VERSION 5.7 ;
  NOWIREEXTENSIONATPIN ON ;
  DIVIDERCHAR "/" ;
  BUSBITCHARS "[]" ;
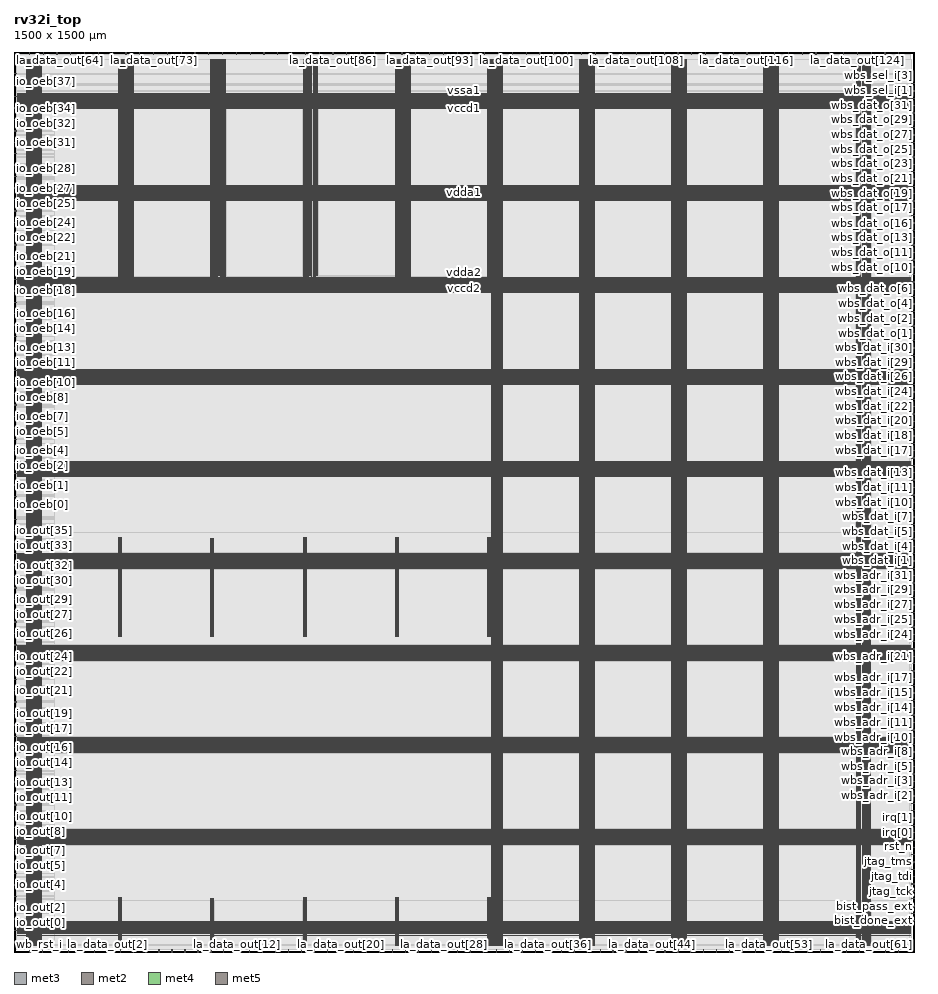
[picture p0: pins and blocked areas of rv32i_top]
MACRO rv32i_top
  CLASS BLOCK ;
  FOREIGN rv32i_top ;
  ORIGIN 0.000 0.000 ;
  SIZE 1500.000 BY 1500.000 ;
  PIN bist_done_ext
    DIRECTION OUTPUT TRISTATE ;
    USE SIGNAL ;
    PORT
      LAYER met3 ;
        RECT 1496.000 51.720 1500.000 52.320 ;
    END
  END bist_done_ext
  PIN bist_mode_ext
    DIRECTION INPUT ;
    USE SIGNAL ;
    PORT
      LAYER met3 ;
        RECT 1496.000 63.960 1500.000 64.560 ;
    END
  END bist_mode_ext
  PIN bist_pass_ext
    DIRECTION OUTPUT TRISTATE ;
    USE SIGNAL ;
    PORT
      LAYER met3 ;
        RECT 1496.000 76.200 1500.000 76.800 ;
    END
  END bist_pass_ext
  PIN clk
    DIRECTION INPUT ;
    USE SIGNAL ;
    ANTENNAGATEAREA 1.286700 ;
    ANTENNADIFFAREA 0.434700 ;
    PORT
      LAYER met3 ;
        RECT 1496.000 88.440 1500.000 89.040 ;
    END
  END clk
  PIN io_oeb[0]
    DIRECTION OUTPUT TRISTATE ;
    USE SIGNAL ;
    PORT
      LAYER met3 ;
        RECT 0.000 758.920 4.000 759.520 ;
    END
  END io_oeb[0]
  PIN io_oeb[10]
    DIRECTION OUTPUT TRISTATE ;
    USE SIGNAL ;
    PORT
      LAYER met3 ;
        RECT 0.000 949.320 4.000 949.920 ;
    END
  END io_oeb[10]
  PIN io_oeb[11]
    DIRECTION OUTPUT TRISTATE ;
    USE SIGNAL ;
    PORT
      LAYER met3 ;
        RECT 0.000 968.360 4.000 968.960 ;
    END
  END io_oeb[11]
  PIN io_oeb[12]
    DIRECTION OUTPUT TRISTATE ;
    USE SIGNAL ;
    PORT
      LAYER met3 ;
        RECT 0.000 987.400 4.000 988.000 ;
    END
  END io_oeb[12]
  PIN io_oeb[13]
    DIRECTION OUTPUT TRISTATE ;
    USE SIGNAL ;
    PORT
      LAYER met3 ;
        RECT 0.000 1006.440 4.000 1007.040 ;
    END
  END io_oeb[13]
  PIN io_oeb[14]
    DIRECTION OUTPUT TRISTATE ;
    USE SIGNAL ;
    PORT
      LAYER met3 ;
        RECT 0.000 1025.480 4.000 1026.080 ;
    END
  END io_oeb[14]
  PIN io_oeb[15]
    DIRECTION OUTPUT TRISTATE ;
    USE SIGNAL ;
    PORT
      LAYER met3 ;
        RECT 0.000 1044.520 4.000 1045.120 ;
    END
  END io_oeb[15]
  PIN io_oeb[16]
    DIRECTION OUTPUT TRISTATE ;
    USE SIGNAL ;
    PORT
      LAYER met3 ;
        RECT 0.000 1063.560 4.000 1064.160 ;
    END
  END io_oeb[16]
  PIN io_oeb[17]
    DIRECTION OUTPUT TRISTATE ;
    USE SIGNAL ;
    PORT
      LAYER met3 ;
        RECT 0.000 1082.600 4.000 1083.200 ;
    END
  END io_oeb[17]
  PIN io_oeb[18]
    DIRECTION OUTPUT TRISTATE ;
    USE SIGNAL ;
    PORT
      LAYER met3 ;
        RECT 0.000 1101.640 4.000 1102.240 ;
    END
  END io_oeb[18]
  PIN io_oeb[19]
    DIRECTION OUTPUT TRISTATE ;
    USE SIGNAL ;
    PORT
      LAYER met3 ;
        RECT 0.000 1120.680 4.000 1121.280 ;
    END
  END io_oeb[19]
  PIN io_oeb[1]
    DIRECTION OUTPUT TRISTATE ;
    USE SIGNAL ;
    PORT
      LAYER met3 ;
        RECT 0.000 777.960 4.000 778.560 ;
    END
  END io_oeb[1]
  PIN io_oeb[20]
    DIRECTION OUTPUT TRISTATE ;
    USE SIGNAL ;
    PORT
      LAYER met3 ;
        RECT 0.000 1139.720 4.000 1140.320 ;
    END
  END io_oeb[20]
  PIN io_oeb[21]
    DIRECTION OUTPUT TRISTATE ;
    USE SIGNAL ;
    PORT
      LAYER met3 ;
        RECT 0.000 1158.760 4.000 1159.360 ;
    END
  END io_oeb[21]
  PIN io_oeb[22]
    DIRECTION OUTPUT TRISTATE ;
    USE SIGNAL ;
    PORT
      LAYER met3 ;
        RECT 0.000 1177.800 4.000 1178.400 ;
    END
  END io_oeb[22]
  PIN io_oeb[23]
    DIRECTION OUTPUT TRISTATE ;
    USE SIGNAL ;
    PORT
      LAYER met3 ;
        RECT 0.000 1196.840 4.000 1197.440 ;
    END
  END io_oeb[23]
  PIN io_oeb[24]
    DIRECTION OUTPUT TRISTATE ;
    USE SIGNAL ;
    PORT
      LAYER met3 ;
        RECT 0.000 1215.880 4.000 1216.480 ;
    END
  END io_oeb[24]
  PIN io_oeb[25]
    DIRECTION OUTPUT TRISTATE ;
    USE SIGNAL ;
    PORT
      LAYER met3 ;
        RECT 0.000 1234.920 4.000 1235.520 ;
    END
  END io_oeb[25]
  PIN io_oeb[26]
    DIRECTION OUTPUT TRISTATE ;
    USE SIGNAL ;
    PORT
      LAYER met3 ;
        RECT 0.000 1253.960 4.000 1254.560 ;
    END
  END io_oeb[26]
  PIN io_oeb[27]
    DIRECTION OUTPUT TRISTATE ;
    USE SIGNAL ;
    PORT
      LAYER met3 ;
        RECT 0.000 1273.000 4.000 1273.600 ;
    END
  END io_oeb[27]
  PIN io_oeb[28]
    DIRECTION OUTPUT TRISTATE ;
    USE SIGNAL ;
    PORT
      LAYER met3 ;
        RECT 0.000 1292.040 4.000 1292.640 ;
    END
  END io_oeb[28]
  PIN io_oeb[29]
    DIRECTION OUTPUT TRISTATE ;
    USE SIGNAL ;
    PORT
      LAYER met3 ;
        RECT 0.000 1311.080 4.000 1311.680 ;
    END
  END io_oeb[29]
  PIN io_oeb[2]
    DIRECTION OUTPUT TRISTATE ;
    USE SIGNAL ;
    PORT
      LAYER met3 ;
        RECT 0.000 797.000 4.000 797.600 ;
    END
  END io_oeb[2]
  PIN io_oeb[30]
    DIRECTION OUTPUT TRISTATE ;
    USE SIGNAL ;
    PORT
      LAYER met3 ;
        RECT 0.000 1330.120 4.000 1330.720 ;
    END
  END io_oeb[30]
  PIN io_oeb[31]
    DIRECTION OUTPUT TRISTATE ;
    USE SIGNAL ;
    PORT
      LAYER met3 ;
        RECT 0.000 1349.160 4.000 1349.760 ;
    END
  END io_oeb[31]
  PIN io_oeb[32]
    DIRECTION OUTPUT TRISTATE ;
    USE SIGNAL ;
    PORT
      LAYER met3 ;
        RECT 0.000 1368.200 4.000 1368.800 ;
    END
  END io_oeb[32]
  PIN io_oeb[33]
    DIRECTION OUTPUT TRISTATE ;
    USE SIGNAL ;
    PORT
      LAYER met3 ;
        RECT 0.000 1387.240 4.000 1387.840 ;
    END
  END io_oeb[33]
  PIN io_oeb[34]
    DIRECTION OUTPUT TRISTATE ;
    USE SIGNAL ;
    PORT
      LAYER met3 ;
        RECT 0.000 1406.280 4.000 1406.880 ;
    END
  END io_oeb[34]
  PIN io_oeb[35]
    DIRECTION OUTPUT TRISTATE ;
    USE SIGNAL ;
    PORT
      LAYER met3 ;
        RECT 0.000 1425.320 4.000 1425.920 ;
    END
  END io_oeb[35]
  PIN io_oeb[36]
    DIRECTION OUTPUT TRISTATE ;
    USE SIGNAL ;
    PORT
      LAYER met3 ;
        RECT 0.000 1444.360 4.000 1444.960 ;
    END
  END io_oeb[36]
  PIN io_oeb[37]
    DIRECTION OUTPUT TRISTATE ;
    USE SIGNAL ;
    PORT
      LAYER met3 ;
        RECT 0.000 1463.400 4.000 1464.000 ;
    END
  END io_oeb[37]
  PIN io_oeb[3]
    DIRECTION OUTPUT TRISTATE ;
    USE SIGNAL ;
    PORT
      LAYER met3 ;
        RECT 0.000 816.040 4.000 816.640 ;
    END
  END io_oeb[3]
  PIN io_oeb[4]
    DIRECTION OUTPUT TRISTATE ;
    USE SIGNAL ;
    PORT
      LAYER met3 ;
        RECT 0.000 835.080 4.000 835.680 ;
    END
  END io_oeb[4]
  PIN io_oeb[5]
    DIRECTION OUTPUT TRISTATE ;
    USE SIGNAL ;
    PORT
      LAYER met3 ;
        RECT 0.000 854.120 4.000 854.720 ;
    END
  END io_oeb[5]
  PIN io_oeb[6]
    DIRECTION OUTPUT TRISTATE ;
    USE SIGNAL ;
    PORT
      LAYER met3 ;
        RECT 0.000 873.160 4.000 873.760 ;
    END
  END io_oeb[6]
  PIN io_oeb[7]
    DIRECTION OUTPUT TRISTATE ;
    USE SIGNAL ;
    PORT
      LAYER met3 ;
        RECT 0.000 892.200 4.000 892.800 ;
    END
  END io_oeb[7]
  PIN io_oeb[8]
    DIRECTION OUTPUT TRISTATE ;
    USE SIGNAL ;
    PORT
      LAYER met3 ;
        RECT 0.000 911.240 4.000 911.840 ;
    END
  END io_oeb[8]
  PIN io_oeb[9]
    DIRECTION OUTPUT TRISTATE ;
    USE SIGNAL ;
    PORT
      LAYER met3 ;
        RECT 0.000 930.280 4.000 930.880 ;
    END
  END io_oeb[9]
  PIN io_out[0]
    DIRECTION OUTPUT TRISTATE ;
    USE SIGNAL ;
    PORT
      LAYER met3 ;
        RECT 0.000 35.400 4.000 36.000 ;
    END
  END io_out[0]
  PIN io_out[10]
    DIRECTION OUTPUT TRISTATE ;
    USE SIGNAL ;
    PORT
      LAYER met3 ;
        RECT 0.000 225.800 4.000 226.400 ;
    END
  END io_out[10]
  PIN io_out[11]
    DIRECTION OUTPUT TRISTATE ;
    USE SIGNAL ;
    PORT
      LAYER met3 ;
        RECT 0.000 244.840 4.000 245.440 ;
    END
  END io_out[11]
  PIN io_out[12]
    DIRECTION OUTPUT TRISTATE ;
    USE SIGNAL ;
    PORT
      LAYER met3 ;
        RECT 0.000 263.880 4.000 264.480 ;
    END
  END io_out[12]
  PIN io_out[13]
    DIRECTION OUTPUT TRISTATE ;
    USE SIGNAL ;
    PORT
      LAYER met3 ;
        RECT 0.000 282.920 4.000 283.520 ;
    END
  END io_out[13]
  PIN io_out[14]
    DIRECTION OUTPUT TRISTATE ;
    USE SIGNAL ;
    PORT
      LAYER met3 ;
        RECT 0.000 301.960 4.000 302.560 ;
    END
  END io_out[14]
  PIN io_out[15]
    DIRECTION OUTPUT TRISTATE ;
    USE SIGNAL ;
    PORT
      LAYER met3 ;
        RECT 0.000 321.000 4.000 321.600 ;
    END
  END io_out[15]
  PIN io_out[16]
    DIRECTION OUTPUT TRISTATE ;
    USE SIGNAL ;
    PORT
      LAYER met3 ;
        RECT 0.000 340.040 4.000 340.640 ;
    END
  END io_out[16]
  PIN io_out[17]
    DIRECTION OUTPUT TRISTATE ;
    USE SIGNAL ;
    PORT
      LAYER met3 ;
        RECT 0.000 359.080 4.000 359.680 ;
    END
  END io_out[17]
  PIN io_out[18]
    DIRECTION OUTPUT TRISTATE ;
    USE SIGNAL ;
    PORT
      LAYER met3 ;
        RECT 0.000 378.120 4.000 378.720 ;
    END
  END io_out[18]
  PIN io_out[19]
    DIRECTION OUTPUT TRISTATE ;
    USE SIGNAL ;
    PORT
      LAYER met3 ;
        RECT 0.000 397.160 4.000 397.760 ;
    END
  END io_out[19]
  PIN io_out[1]
    DIRECTION OUTPUT TRISTATE ;
    USE SIGNAL ;
    PORT
      LAYER met3 ;
        RECT 0.000 54.440 4.000 55.040 ;
    END
  END io_out[1]
  PIN io_out[20]
    DIRECTION OUTPUT TRISTATE ;
    USE SIGNAL ;
    PORT
      LAYER met3 ;
        RECT 0.000 416.200 4.000 416.800 ;
    END
  END io_out[20]
  PIN io_out[21]
    DIRECTION OUTPUT TRISTATE ;
    USE SIGNAL ;
    PORT
      LAYER met3 ;
        RECT 0.000 435.240 4.000 435.840 ;
    END
  END io_out[21]
  PIN io_out[22]
    DIRECTION OUTPUT TRISTATE ;
    USE SIGNAL ;
    PORT
      LAYER met3 ;
        RECT 0.000 454.280 4.000 454.880 ;
    END
  END io_out[22]
  PIN io_out[23]
    DIRECTION OUTPUT TRISTATE ;
    USE SIGNAL ;
    PORT
      LAYER met3 ;
        RECT 0.000 473.320 4.000 473.920 ;
    END
  END io_out[23]
  PIN io_out[24]
    DIRECTION OUTPUT TRISTATE ;
    USE SIGNAL ;
    PORT
      LAYER met3 ;
        RECT 0.000 492.360 4.000 492.960 ;
    END
  END io_out[24]
  PIN io_out[25]
    DIRECTION OUTPUT TRISTATE ;
    USE SIGNAL ;
    PORT
      LAYER met3 ;
        RECT 0.000 511.400 4.000 512.000 ;
    END
  END io_out[25]
  PIN io_out[26]
    DIRECTION OUTPUT TRISTATE ;
    USE SIGNAL ;
    PORT
      LAYER met3 ;
        RECT 0.000 530.440 4.000 531.040 ;
    END
  END io_out[26]
  PIN io_out[27]
    DIRECTION OUTPUT TRISTATE ;
    USE SIGNAL ;
    PORT
      LAYER met3 ;
        RECT 0.000 549.480 4.000 550.080 ;
    END
  END io_out[27]
  PIN io_out[28]
    DIRECTION OUTPUT TRISTATE ;
    USE SIGNAL ;
    PORT
      LAYER met3 ;
        RECT 0.000 568.520 4.000 569.120 ;
    END
  END io_out[28]
  PIN io_out[29]
    DIRECTION OUTPUT TRISTATE ;
    USE SIGNAL ;
    PORT
      LAYER met3 ;
        RECT 0.000 587.560 4.000 588.160 ;
    END
  END io_out[29]
  PIN io_out[2]
    DIRECTION OUTPUT TRISTATE ;
    USE SIGNAL ;
    PORT
      LAYER met3 ;
        RECT 0.000 73.480 4.000 74.080 ;
    END
  END io_out[2]
  PIN io_out[30]
    DIRECTION OUTPUT TRISTATE ;
    USE SIGNAL ;
    PORT
      LAYER met3 ;
        RECT 0.000 606.600 4.000 607.200 ;
    END
  END io_out[30]
  PIN io_out[31]
    DIRECTION OUTPUT TRISTATE ;
    USE SIGNAL ;
    PORT
      LAYER met3 ;
        RECT 0.000 625.640 4.000 626.240 ;
    END
  END io_out[31]
  PIN io_out[32]
    DIRECTION OUTPUT TRISTATE ;
    USE SIGNAL ;
    PORT
      LAYER met3 ;
        RECT 0.000 644.680 4.000 645.280 ;
    END
  END io_out[32]
  PIN io_out[33]
    DIRECTION OUTPUT TRISTATE ;
    USE SIGNAL ;
    PORT
      LAYER met3 ;
        RECT 0.000 663.720 4.000 664.320 ;
    END
  END io_out[33]
  PIN io_out[34]
    DIRECTION OUTPUT TRISTATE ;
    USE SIGNAL ;
    PORT
      LAYER met3 ;
        RECT 0.000 682.760 4.000 683.360 ;
    END
  END io_out[34]
  PIN io_out[35]
    DIRECTION OUTPUT TRISTATE ;
    USE SIGNAL ;
    PORT
      LAYER met3 ;
        RECT 0.000 701.800 4.000 702.400 ;
    END
  END io_out[35]
  PIN io_out[36]
    DIRECTION OUTPUT TRISTATE ;
    USE SIGNAL ;
    PORT
      LAYER met3 ;
        RECT 0.000 720.840 4.000 721.440 ;
    END
  END io_out[36]
  PIN io_out[37]
    DIRECTION OUTPUT TRISTATE ;
    USE SIGNAL ;
    PORT
      LAYER met3 ;
        RECT 0.000 739.880 4.000 740.480 ;
    END
  END io_out[37]
  PIN io_out[3]
    DIRECTION OUTPUT TRISTATE ;
    USE SIGNAL ;
    PORT
      LAYER met3 ;
        RECT 0.000 92.520 4.000 93.120 ;
    END
  END io_out[3]
  PIN io_out[4]
    DIRECTION OUTPUT TRISTATE ;
    USE SIGNAL ;
    PORT
      LAYER met3 ;
        RECT 0.000 111.560 4.000 112.160 ;
    END
  END io_out[4]
  PIN io_out[5]
    DIRECTION OUTPUT TRISTATE ;
    USE SIGNAL ;
    PORT
      LAYER met3 ;
        RECT 0.000 130.600 4.000 131.200 ;
    END
  END io_out[5]
  PIN io_out[6]
    DIRECTION OUTPUT TRISTATE ;
    USE SIGNAL ;
    PORT
      LAYER met3 ;
        RECT 0.000 149.640 4.000 150.240 ;
    END
  END io_out[6]
  PIN io_out[7]
    DIRECTION OUTPUT TRISTATE ;
    USE SIGNAL ;
    PORT
      LAYER met3 ;
        RECT 0.000 168.680 4.000 169.280 ;
    END
  END io_out[7]
  PIN io_out[8]
    DIRECTION OUTPUT TRISTATE ;
    USE SIGNAL ;
    PORT
      LAYER met3 ;
        RECT 0.000 187.720 4.000 188.320 ;
    END
  END io_out[8]
  PIN io_out[9]
    DIRECTION OUTPUT TRISTATE ;
    USE SIGNAL ;
    PORT
      LAYER met3 ;
        RECT 0.000 206.760 4.000 207.360 ;
    END
  END io_out[9]
  PIN irq[0]
    DIRECTION OUTPUT TRISTATE ;
    USE SIGNAL ;
    PORT
      LAYER met3 ;
        RECT 1496.000 198.600 1500.000 199.200 ;
    END
  END irq[0]
  PIN irq[1]
    DIRECTION OUTPUT TRISTATE ;
    USE SIGNAL ;
    PORT
      LAYER met3 ;
        RECT 1496.000 210.840 1500.000 211.440 ;
    END
  END irq[1]
  PIN irq[2]
    DIRECTION OUTPUT TRISTATE ;
    USE SIGNAL ;
    PORT
      LAYER met3 ;
        RECT 1496.000 223.080 1500.000 223.680 ;
    END
  END irq[2]
  PIN jtag_tck
    DIRECTION INPUT ;
    USE SIGNAL ;
    PORT
      LAYER met3 ;
        RECT 1496.000 100.680 1500.000 101.280 ;
    END
  END jtag_tck
  PIN jtag_tdi
    DIRECTION INPUT ;
    USE SIGNAL ;
    PORT
      LAYER met3 ;
        RECT 1496.000 112.920 1500.000 113.520 ;
    END
  END jtag_tdi
  PIN jtag_tdo
    DIRECTION OUTPUT TRISTATE ;
    USE SIGNAL ;
    PORT
      LAYER met3 ;
        RECT 1496.000 125.160 1500.000 125.760 ;
    END
  END jtag_tdo
  PIN jtag_tms
    DIRECTION INPUT ;
    USE SIGNAL ;
    PORT
      LAYER met3 ;
        RECT 1496.000 137.400 1500.000 138.000 ;
    END
  END jtag_tms
  PIN jtag_trst_n
    DIRECTION INPUT ;
    USE SIGNAL ;
    PORT
      LAYER met3 ;
        RECT 1496.000 149.640 1500.000 150.240 ;
    END
  END jtag_trst_n
  PIN la_data_out[0]
    DIRECTION OUTPUT TRISTATE ;
    USE SIGNAL ;
    PORT
      LAYER met2 ;
        RECT 111.870 0.000 112.150 4.000 ;
    END
  END la_data_out[0]
  PIN la_data_out[100]
    DIRECTION OUTPUT TRISTATE ;
    USE SIGNAL ;
    PORT
      LAYER met2 ;
        RECT 853.390 1496.000 853.670 1500.000 ;
    END
  END la_data_out[100]
  PIN la_data_out[101]
    DIRECTION OUTPUT TRISTATE ;
    USE SIGNAL ;
    PORT
      LAYER met2 ;
        RECT 876.390 1496.000 876.670 1500.000 ;
    END
  END la_data_out[101]
  PIN la_data_out[102]
    DIRECTION OUTPUT TRISTATE ;
    USE SIGNAL ;
    PORT
      LAYER met2 ;
        RECT 899.390 1496.000 899.670 1500.000 ;
    END
  END la_data_out[102]
  PIN la_data_out[103]
    DIRECTION OUTPUT TRISTATE ;
    USE SIGNAL ;
    PORT
      LAYER met2 ;
        RECT 922.390 1496.000 922.670 1500.000 ;
    END
  END la_data_out[103]
  PIN la_data_out[104]
    DIRECTION OUTPUT TRISTATE ;
    USE SIGNAL ;
    PORT
      LAYER met2 ;
        RECT 945.390 1496.000 945.670 1500.000 ;
    END
  END la_data_out[104]
  PIN la_data_out[105]
    DIRECTION OUTPUT TRISTATE ;
    USE SIGNAL ;
    PORT
      LAYER met2 ;
        RECT 968.390 1496.000 968.670 1500.000 ;
    END
  END la_data_out[105]
  PIN la_data_out[106]
    DIRECTION OUTPUT TRISTATE ;
    USE SIGNAL ;
    PORT
      LAYER met2 ;
        RECT 991.390 1496.000 991.670 1500.000 ;
    END
  END la_data_out[106]
  PIN la_data_out[107]
    DIRECTION OUTPUT TRISTATE ;
    USE SIGNAL ;
    PORT
      LAYER met2 ;
        RECT 1014.390 1496.000 1014.670 1500.000 ;
    END
  END la_data_out[107]
  PIN la_data_out[108]
    DIRECTION OUTPUT TRISTATE ;
    USE SIGNAL ;
    PORT
      LAYER met2 ;
        RECT 1037.390 1496.000 1037.670 1500.000 ;
    END
  END la_data_out[108]
  PIN la_data_out[109]
    DIRECTION OUTPUT TRISTATE ;
    USE SIGNAL ;
    PORT
      LAYER met2 ;
        RECT 1060.390 1496.000 1060.670 1500.000 ;
    END
  END la_data_out[109]
  PIN la_data_out[10]
    DIRECTION OUTPUT TRISTATE ;
    USE SIGNAL ;
    PORT
      LAYER met2 ;
        RECT 328.070 0.000 328.350 4.000 ;
    END
  END la_data_out[10]
  PIN la_data_out[110]
    DIRECTION OUTPUT TRISTATE ;
    USE SIGNAL ;
    PORT
      LAYER met2 ;
        RECT 1083.390 1496.000 1083.670 1500.000 ;
    END
  END la_data_out[110]
  PIN la_data_out[111]
    DIRECTION OUTPUT TRISTATE ;
    USE SIGNAL ;
    PORT
      LAYER met2 ;
        RECT 1106.390 1496.000 1106.670 1500.000 ;
    END
  END la_data_out[111]
  PIN la_data_out[112]
    DIRECTION OUTPUT TRISTATE ;
    USE SIGNAL ;
    PORT
      LAYER met2 ;
        RECT 1129.390 1496.000 1129.670 1500.000 ;
    END
  END la_data_out[112]
  PIN la_data_out[113]
    DIRECTION OUTPUT TRISTATE ;
    USE SIGNAL ;
    PORT
      LAYER met2 ;
        RECT 1152.390 1496.000 1152.670 1500.000 ;
    END
  END la_data_out[113]
  PIN la_data_out[114]
    DIRECTION OUTPUT TRISTATE ;
    USE SIGNAL ;
    PORT
      LAYER met2 ;
        RECT 1175.390 1496.000 1175.670 1500.000 ;
    END
  END la_data_out[114]
  PIN la_data_out[115]
    DIRECTION OUTPUT TRISTATE ;
    USE SIGNAL ;
    PORT
      LAYER met2 ;
        RECT 1198.390 1496.000 1198.670 1500.000 ;
    END
  END la_data_out[115]
  PIN la_data_out[116]
    DIRECTION OUTPUT TRISTATE ;
    USE SIGNAL ;
    PORT
      LAYER met2 ;
        RECT 1221.390 1496.000 1221.670 1500.000 ;
    END
  END la_data_out[116]
  PIN la_data_out[117]
    DIRECTION OUTPUT TRISTATE ;
    USE SIGNAL ;
    PORT
      LAYER met2 ;
        RECT 1244.390 1496.000 1244.670 1500.000 ;
    END
  END la_data_out[117]
  PIN la_data_out[118]
    DIRECTION OUTPUT TRISTATE ;
    USE SIGNAL ;
    PORT
      LAYER met2 ;
        RECT 1267.390 1496.000 1267.670 1500.000 ;
    END
  END la_data_out[118]
  PIN la_data_out[119]
    DIRECTION OUTPUT TRISTATE ;
    USE SIGNAL ;
    PORT
      LAYER met2 ;
        RECT 1290.390 1496.000 1290.670 1500.000 ;
    END
  END la_data_out[119]
  PIN la_data_out[11]
    DIRECTION OUTPUT TRISTATE ;
    USE SIGNAL ;
    PORT
      LAYER met2 ;
        RECT 349.690 0.000 349.970 4.000 ;
    END
  END la_data_out[11]
  PIN la_data_out[120]
    DIRECTION OUTPUT TRISTATE ;
    USE SIGNAL ;
    PORT
      LAYER met2 ;
        RECT 1313.390 1496.000 1313.670 1500.000 ;
    END
  END la_data_out[120]
  PIN la_data_out[121]
    DIRECTION OUTPUT TRISTATE ;
    USE SIGNAL ;
    PORT
      LAYER met2 ;
        RECT 1336.390 1496.000 1336.670 1500.000 ;
    END
  END la_data_out[121]
  PIN la_data_out[122]
    DIRECTION OUTPUT TRISTATE ;
    USE SIGNAL ;
    PORT
      LAYER met2 ;
        RECT 1359.390 1496.000 1359.670 1500.000 ;
    END
  END la_data_out[122]
  PIN la_data_out[123]
    DIRECTION OUTPUT TRISTATE ;
    USE SIGNAL ;
    PORT
      LAYER met2 ;
        RECT 1382.390 1496.000 1382.670 1500.000 ;
    END
  END la_data_out[123]
  PIN la_data_out[124]
    DIRECTION OUTPUT TRISTATE ;
    USE SIGNAL ;
    PORT
      LAYER met2 ;
        RECT 1405.390 1496.000 1405.670 1500.000 ;
    END
  END la_data_out[124]
  PIN la_data_out[125]
    DIRECTION OUTPUT TRISTATE ;
    USE SIGNAL ;
    PORT
      LAYER met2 ;
        RECT 1428.390 1496.000 1428.670 1500.000 ;
    END
  END la_data_out[125]
  PIN la_data_out[126]
    DIRECTION OUTPUT TRISTATE ;
    USE SIGNAL ;
    PORT
      LAYER met2 ;
        RECT 1451.390 1496.000 1451.670 1500.000 ;
    END
  END la_data_out[126]
  PIN la_data_out[127]
    DIRECTION OUTPUT TRISTATE ;
    USE SIGNAL ;
    PORT
      LAYER met2 ;
        RECT 1474.390 1496.000 1474.670 1500.000 ;
    END
  END la_data_out[127]
  PIN la_data_out[12]
    DIRECTION OUTPUT TRISTATE ;
    USE SIGNAL ;
    PORT
      LAYER met2 ;
        RECT 371.310 0.000 371.590 4.000 ;
    END
  END la_data_out[12]
  PIN la_data_out[13]
    DIRECTION OUTPUT TRISTATE ;
    USE SIGNAL ;
    PORT
      LAYER met2 ;
        RECT 392.930 0.000 393.210 4.000 ;
    END
  END la_data_out[13]
  PIN la_data_out[14]
    DIRECTION OUTPUT TRISTATE ;
    USE SIGNAL ;
    PORT
      LAYER met2 ;
        RECT 414.550 0.000 414.830 4.000 ;
    END
  END la_data_out[14]
  PIN la_data_out[15]
    DIRECTION OUTPUT TRISTATE ;
    USE SIGNAL ;
    PORT
      LAYER met2 ;
        RECT 436.170 0.000 436.450 4.000 ;
    END
  END la_data_out[15]
  PIN la_data_out[16]
    DIRECTION OUTPUT TRISTATE ;
    USE SIGNAL ;
    PORT
      LAYER met2 ;
        RECT 457.790 0.000 458.070 4.000 ;
    END
  END la_data_out[16]
  PIN la_data_out[17]
    DIRECTION OUTPUT TRISTATE ;
    USE SIGNAL ;
    PORT
      LAYER met2 ;
        RECT 479.410 0.000 479.690 4.000 ;
    END
  END la_data_out[17]
  PIN la_data_out[18]
    DIRECTION OUTPUT TRISTATE ;
    USE SIGNAL ;
    PORT
      LAYER met2 ;
        RECT 501.030 0.000 501.310 4.000 ;
    END
  END la_data_out[18]
  PIN la_data_out[19]
    DIRECTION OUTPUT TRISTATE ;
    USE SIGNAL ;
    PORT
      LAYER met2 ;
        RECT 522.650 0.000 522.930 4.000 ;
    END
  END la_data_out[19]
  PIN la_data_out[1]
    DIRECTION OUTPUT TRISTATE ;
    USE SIGNAL ;
    PORT
      LAYER met2 ;
        RECT 133.490 0.000 133.770 4.000 ;
    END
  END la_data_out[1]
  PIN la_data_out[20]
    DIRECTION OUTPUT TRISTATE ;
    USE SIGNAL ;
    PORT
      LAYER met2 ;
        RECT 544.270 0.000 544.550 4.000 ;
    END
  END la_data_out[20]
  PIN la_data_out[21]
    DIRECTION OUTPUT TRISTATE ;
    USE SIGNAL ;
    PORT
      LAYER met2 ;
        RECT 565.890 0.000 566.170 4.000 ;
    END
  END la_data_out[21]
  PIN la_data_out[22]
    DIRECTION OUTPUT TRISTATE ;
    USE SIGNAL ;
    PORT
      LAYER met2 ;
        RECT 587.510 0.000 587.790 4.000 ;
    END
  END la_data_out[22]
  PIN la_data_out[23]
    DIRECTION OUTPUT TRISTATE ;
    USE SIGNAL ;
    PORT
      LAYER met2 ;
        RECT 609.130 0.000 609.410 4.000 ;
    END
  END la_data_out[23]
  PIN la_data_out[24]
    DIRECTION OUTPUT TRISTATE ;
    USE SIGNAL ;
    PORT
      LAYER met2 ;
        RECT 630.750 0.000 631.030 4.000 ;
    END
  END la_data_out[24]
  PIN la_data_out[25]
    DIRECTION OUTPUT TRISTATE ;
    USE SIGNAL ;
    PORT
      LAYER met2 ;
        RECT 652.370 0.000 652.650 4.000 ;
    END
  END la_data_out[25]
  PIN la_data_out[26]
    DIRECTION OUTPUT TRISTATE ;
    USE SIGNAL ;
    PORT
      LAYER met2 ;
        RECT 673.990 0.000 674.270 4.000 ;
    END
  END la_data_out[26]
  PIN la_data_out[27]
    DIRECTION OUTPUT TRISTATE ;
    USE SIGNAL ;
    PORT
      LAYER met2 ;
        RECT 695.610 0.000 695.890 4.000 ;
    END
  END la_data_out[27]
  PIN la_data_out[28]
    DIRECTION OUTPUT TRISTATE ;
    USE SIGNAL ;
    PORT
      LAYER met2 ;
        RECT 717.230 0.000 717.510 4.000 ;
    END
  END la_data_out[28]
  PIN la_data_out[29]
    DIRECTION OUTPUT TRISTATE ;
    USE SIGNAL ;
    PORT
      LAYER met2 ;
        RECT 738.850 0.000 739.130 4.000 ;
    END
  END la_data_out[29]
  PIN la_data_out[2]
    DIRECTION OUTPUT TRISTATE ;
    USE SIGNAL ;
    PORT
      LAYER met2 ;
        RECT 155.110 0.000 155.390 4.000 ;
    END
  END la_data_out[2]
  PIN la_data_out[30]
    DIRECTION OUTPUT TRISTATE ;
    USE SIGNAL ;
    PORT
      LAYER met2 ;
        RECT 760.470 0.000 760.750 4.000 ;
    END
  END la_data_out[30]
  PIN la_data_out[31]
    DIRECTION OUTPUT TRISTATE ;
    USE SIGNAL ;
    PORT
      LAYER met2 ;
        RECT 782.090 0.000 782.370 4.000 ;
    END
  END la_data_out[31]
  PIN la_data_out[32]
    DIRECTION OUTPUT TRISTATE ;
    USE SIGNAL ;
    PORT
      LAYER met2 ;
        RECT 803.710 0.000 803.990 4.000 ;
    END
  END la_data_out[32]
  PIN la_data_out[33]
    DIRECTION OUTPUT TRISTATE ;
    USE SIGNAL ;
    PORT
      LAYER met2 ;
        RECT 825.330 0.000 825.610 4.000 ;
    END
  END la_data_out[33]
  PIN la_data_out[34]
    DIRECTION OUTPUT TRISTATE ;
    USE SIGNAL ;
    PORT
      LAYER met2 ;
        RECT 846.950 0.000 847.230 4.000 ;
    END
  END la_data_out[34]
  PIN la_data_out[35]
    DIRECTION OUTPUT TRISTATE ;
    USE SIGNAL ;
    PORT
      LAYER met2 ;
        RECT 868.570 0.000 868.850 4.000 ;
    END
  END la_data_out[35]
  PIN la_data_out[36]
    DIRECTION OUTPUT TRISTATE ;
    USE SIGNAL ;
    PORT
      LAYER met2 ;
        RECT 890.190 0.000 890.470 4.000 ;
    END
  END la_data_out[36]
  PIN la_data_out[37]
    DIRECTION OUTPUT TRISTATE ;
    USE SIGNAL ;
    PORT
      LAYER met2 ;
        RECT 911.810 0.000 912.090 4.000 ;
    END
  END la_data_out[37]
  PIN la_data_out[38]
    DIRECTION OUTPUT TRISTATE ;
    USE SIGNAL ;
    PORT
      LAYER met2 ;
        RECT 933.430 0.000 933.710 4.000 ;
    END
  END la_data_out[38]
  PIN la_data_out[39]
    DIRECTION OUTPUT TRISTATE ;
    USE SIGNAL ;
    PORT
      LAYER met2 ;
        RECT 955.050 0.000 955.330 4.000 ;
    END
  END la_data_out[39]
  PIN la_data_out[3]
    DIRECTION OUTPUT TRISTATE ;
    USE SIGNAL ;
    PORT
      LAYER met2 ;
        RECT 176.730 0.000 177.010 4.000 ;
    END
  END la_data_out[3]
  PIN la_data_out[40]
    DIRECTION OUTPUT TRISTATE ;
    USE SIGNAL ;
    PORT
      LAYER met2 ;
        RECT 976.670 0.000 976.950 4.000 ;
    END
  END la_data_out[40]
  PIN la_data_out[41]
    DIRECTION OUTPUT TRISTATE ;
    USE SIGNAL ;
    PORT
      LAYER met2 ;
        RECT 998.290 0.000 998.570 4.000 ;
    END
  END la_data_out[41]
  PIN la_data_out[42]
    DIRECTION OUTPUT TRISTATE ;
    USE SIGNAL ;
    PORT
      LAYER met2 ;
        RECT 1019.910 0.000 1020.190 4.000 ;
    END
  END la_data_out[42]
  PIN la_data_out[43]
    DIRECTION OUTPUT TRISTATE ;
    USE SIGNAL ;
    PORT
      LAYER met2 ;
        RECT 1041.530 0.000 1041.810 4.000 ;
    END
  END la_data_out[43]
  PIN la_data_out[44]
    DIRECTION OUTPUT TRISTATE ;
    USE SIGNAL ;
    PORT
      LAYER met2 ;
        RECT 1063.150 0.000 1063.430 4.000 ;
    END
  END la_data_out[44]
  PIN la_data_out[45]
    DIRECTION OUTPUT TRISTATE ;
    USE SIGNAL ;
    PORT
      LAYER met2 ;
        RECT 1084.770 0.000 1085.050 4.000 ;
    END
  END la_data_out[45]
  PIN la_data_out[46]
    DIRECTION OUTPUT TRISTATE ;
    USE SIGNAL ;
    PORT
      LAYER met2 ;
        RECT 1106.390 0.000 1106.670 4.000 ;
    END
  END la_data_out[46]
  PIN la_data_out[47]
    DIRECTION OUTPUT TRISTATE ;
    USE SIGNAL ;
    PORT
      LAYER met2 ;
        RECT 1128.010 0.000 1128.290 4.000 ;
    END
  END la_data_out[47]
  PIN la_data_out[48]
    DIRECTION OUTPUT TRISTATE ;
    USE SIGNAL ;
    PORT
      LAYER met2 ;
        RECT 1149.630 0.000 1149.910 4.000 ;
    END
  END la_data_out[48]
  PIN la_data_out[49]
    DIRECTION OUTPUT TRISTATE ;
    USE SIGNAL ;
    PORT
      LAYER met2 ;
        RECT 1171.250 0.000 1171.530 4.000 ;
    END
  END la_data_out[49]
  PIN la_data_out[4]
    DIRECTION OUTPUT TRISTATE ;
    USE SIGNAL ;
    PORT
      LAYER met2 ;
        RECT 198.350 0.000 198.630 4.000 ;
    END
  END la_data_out[4]
  PIN la_data_out[50]
    DIRECTION OUTPUT TRISTATE ;
    USE SIGNAL ;
    PORT
      LAYER met2 ;
        RECT 1192.870 0.000 1193.150 4.000 ;
    END
  END la_data_out[50]
  PIN la_data_out[51]
    DIRECTION OUTPUT TRISTATE ;
    USE SIGNAL ;
    PORT
      LAYER met2 ;
        RECT 1214.490 0.000 1214.770 4.000 ;
    END
  END la_data_out[51]
  PIN la_data_out[52]
    DIRECTION OUTPUT TRISTATE ;
    USE SIGNAL ;
    PORT
      LAYER met2 ;
        RECT 1236.110 0.000 1236.390 4.000 ;
    END
  END la_data_out[52]
  PIN la_data_out[53]
    DIRECTION OUTPUT TRISTATE ;
    USE SIGNAL ;
    PORT
      LAYER met2 ;
        RECT 1257.730 0.000 1258.010 4.000 ;
    END
  END la_data_out[53]
  PIN la_data_out[54]
    DIRECTION OUTPUT TRISTATE ;
    USE SIGNAL ;
    PORT
      LAYER met2 ;
        RECT 1279.350 0.000 1279.630 4.000 ;
    END
  END la_data_out[54]
  PIN la_data_out[55]
    DIRECTION OUTPUT TRISTATE ;
    USE SIGNAL ;
    PORT
      LAYER met2 ;
        RECT 1300.970 0.000 1301.250 4.000 ;
    END
  END la_data_out[55]
  PIN la_data_out[56]
    DIRECTION OUTPUT TRISTATE ;
    USE SIGNAL ;
    PORT
      LAYER met2 ;
        RECT 1322.590 0.000 1322.870 4.000 ;
    END
  END la_data_out[56]
  PIN la_data_out[57]
    DIRECTION OUTPUT TRISTATE ;
    USE SIGNAL ;
    PORT
      LAYER met2 ;
        RECT 1344.210 0.000 1344.490 4.000 ;
    END
  END la_data_out[57]
  PIN la_data_out[58]
    DIRECTION OUTPUT TRISTATE ;
    USE SIGNAL ;
    PORT
      LAYER met2 ;
        RECT 1365.830 0.000 1366.110 4.000 ;
    END
  END la_data_out[58]
  PIN la_data_out[59]
    DIRECTION OUTPUT TRISTATE ;
    USE SIGNAL ;
    PORT
      LAYER met2 ;
        RECT 1387.450 0.000 1387.730 4.000 ;
    END
  END la_data_out[59]
  PIN la_data_out[5]
    DIRECTION OUTPUT TRISTATE ;
    USE SIGNAL ;
    PORT
      LAYER met2 ;
        RECT 219.970 0.000 220.250 4.000 ;
    END
  END la_data_out[5]
  PIN la_data_out[60]
    DIRECTION OUTPUT TRISTATE ;
    USE SIGNAL ;
    PORT
      LAYER met2 ;
        RECT 1409.070 0.000 1409.350 4.000 ;
    END
  END la_data_out[60]
  PIN la_data_out[61]
    DIRECTION OUTPUT TRISTATE ;
    USE SIGNAL ;
    PORT
      LAYER met2 ;
        RECT 1430.690 0.000 1430.970 4.000 ;
    END
  END la_data_out[61]
  PIN la_data_out[62]
    DIRECTION OUTPUT TRISTATE ;
    USE SIGNAL ;
    PORT
      LAYER met2 ;
        RECT 1452.310 0.000 1452.590 4.000 ;
    END
  END la_data_out[62]
  PIN la_data_out[63]
    DIRECTION OUTPUT TRISTATE ;
    USE SIGNAL ;
    PORT
      LAYER met2 ;
        RECT 1473.930 0.000 1474.210 4.000 ;
    END
  END la_data_out[63]
  PIN la_data_out[64]
    DIRECTION OUTPUT TRISTATE ;
    USE SIGNAL ;
    PORT
      LAYER met2 ;
        RECT 25.390 1496.000 25.670 1500.000 ;
    END
  END la_data_out[64]
  PIN la_data_out[65]
    DIRECTION OUTPUT TRISTATE ;
    USE SIGNAL ;
    PORT
      LAYER met2 ;
        RECT 48.390 1496.000 48.670 1500.000 ;
    END
  END la_data_out[65]
  PIN la_data_out[66]
    DIRECTION OUTPUT TRISTATE ;
    USE SIGNAL ;
    PORT
      LAYER met2 ;
        RECT 71.390 1496.000 71.670 1500.000 ;
    END
  END la_data_out[66]
  PIN la_data_out[67]
    DIRECTION OUTPUT TRISTATE ;
    USE SIGNAL ;
    PORT
      LAYER met2 ;
        RECT 94.390 1496.000 94.670 1500.000 ;
    END
  END la_data_out[67]
  PIN la_data_out[68]
    DIRECTION OUTPUT TRISTATE ;
    USE SIGNAL ;
    PORT
      LAYER met2 ;
        RECT 117.390 1496.000 117.670 1500.000 ;
    END
  END la_data_out[68]
  PIN la_data_out[69]
    DIRECTION OUTPUT TRISTATE ;
    USE SIGNAL ;
    PORT
      LAYER met2 ;
        RECT 140.390 1496.000 140.670 1500.000 ;
    END
  END la_data_out[69]
  PIN la_data_out[6]
    DIRECTION OUTPUT TRISTATE ;
    USE SIGNAL ;
    PORT
      LAYER met2 ;
        RECT 241.590 0.000 241.870 4.000 ;
    END
  END la_data_out[6]
  PIN la_data_out[70]
    DIRECTION OUTPUT TRISTATE ;
    USE SIGNAL ;
    PORT
      LAYER met2 ;
        RECT 163.390 1496.000 163.670 1500.000 ;
    END
  END la_data_out[70]
  PIN la_data_out[71]
    DIRECTION OUTPUT TRISTATE ;
    USE SIGNAL ;
    PORT
      LAYER met2 ;
        RECT 186.390 1496.000 186.670 1500.000 ;
    END
  END la_data_out[71]
  PIN la_data_out[72]
    DIRECTION OUTPUT TRISTATE ;
    USE SIGNAL ;
    PORT
      LAYER met2 ;
        RECT 209.390 1496.000 209.670 1500.000 ;
    END
  END la_data_out[72]
  PIN la_data_out[73]
    DIRECTION OUTPUT TRISTATE ;
    USE SIGNAL ;
    PORT
      LAYER met2 ;
        RECT 232.390 1496.000 232.670 1500.000 ;
    END
  END la_data_out[73]
  PIN la_data_out[74]
    DIRECTION OUTPUT TRISTATE ;
    USE SIGNAL ;
    PORT
      LAYER met2 ;
        RECT 255.390 1496.000 255.670 1500.000 ;
    END
  END la_data_out[74]
  PIN la_data_out[75]
    DIRECTION OUTPUT TRISTATE ;
    USE SIGNAL ;
    PORT
      LAYER met2 ;
        RECT 278.390 1496.000 278.670 1500.000 ;
    END
  END la_data_out[75]
  PIN la_data_out[76]
    DIRECTION OUTPUT TRISTATE ;
    USE SIGNAL ;
    PORT
      LAYER met2 ;
        RECT 301.390 1496.000 301.670 1500.000 ;
    END
  END la_data_out[76]
  PIN la_data_out[77]
    DIRECTION OUTPUT TRISTATE ;
    USE SIGNAL ;
    PORT
      LAYER met2 ;
        RECT 324.390 1496.000 324.670 1500.000 ;
    END
  END la_data_out[77]
  PIN la_data_out[78]
    DIRECTION OUTPUT TRISTATE ;
    USE SIGNAL ;
    PORT
      LAYER met2 ;
        RECT 347.390 1496.000 347.670 1500.000 ;
    END
  END la_data_out[78]
  PIN la_data_out[79]
    DIRECTION OUTPUT TRISTATE ;
    USE SIGNAL ;
    PORT
      LAYER met2 ;
        RECT 370.390 1496.000 370.670 1500.000 ;
    END
  END la_data_out[79]
  PIN la_data_out[7]
    DIRECTION OUTPUT TRISTATE ;
    USE SIGNAL ;
    PORT
      LAYER met2 ;
        RECT 263.210 0.000 263.490 4.000 ;
    END
  END la_data_out[7]
  PIN la_data_out[80]
    DIRECTION OUTPUT TRISTATE ;
    USE SIGNAL ;
    PORT
      LAYER met2 ;
        RECT 393.390 1496.000 393.670 1500.000 ;
    END
  END la_data_out[80]
  PIN la_data_out[81]
    DIRECTION OUTPUT TRISTATE ;
    USE SIGNAL ;
    PORT
      LAYER met2 ;
        RECT 416.390 1496.000 416.670 1500.000 ;
    END
  END la_data_out[81]
  PIN la_data_out[82]
    DIRECTION OUTPUT TRISTATE ;
    USE SIGNAL ;
    PORT
      LAYER met2 ;
        RECT 439.390 1496.000 439.670 1500.000 ;
    END
  END la_data_out[82]
  PIN la_data_out[83]
    DIRECTION OUTPUT TRISTATE ;
    USE SIGNAL ;
    PORT
      LAYER met2 ;
        RECT 462.390 1496.000 462.670 1500.000 ;
    END
  END la_data_out[83]
  PIN la_data_out[84]
    DIRECTION OUTPUT TRISTATE ;
    USE SIGNAL ;
    PORT
      LAYER met2 ;
        RECT 485.390 1496.000 485.670 1500.000 ;
    END
  END la_data_out[84]
  PIN la_data_out[85]
    DIRECTION OUTPUT TRISTATE ;
    USE SIGNAL ;
    PORT
      LAYER met2 ;
        RECT 508.390 1496.000 508.670 1500.000 ;
    END
  END la_data_out[85]
  PIN la_data_out[86]
    DIRECTION OUTPUT TRISTATE ;
    USE SIGNAL ;
    PORT
      LAYER met2 ;
        RECT 531.390 1496.000 531.670 1500.000 ;
    END
  END la_data_out[86]
  PIN la_data_out[87]
    DIRECTION OUTPUT TRISTATE ;
    USE SIGNAL ;
    PORT
      LAYER met2 ;
        RECT 554.390 1496.000 554.670 1500.000 ;
    END
  END la_data_out[87]
  PIN la_data_out[88]
    DIRECTION OUTPUT TRISTATE ;
    USE SIGNAL ;
    PORT
      LAYER met2 ;
        RECT 577.390 1496.000 577.670 1500.000 ;
    END
  END la_data_out[88]
  PIN la_data_out[89]
    DIRECTION OUTPUT TRISTATE ;
    USE SIGNAL ;
    PORT
      LAYER met2 ;
        RECT 600.390 1496.000 600.670 1500.000 ;
    END
  END la_data_out[89]
  PIN la_data_out[8]
    DIRECTION OUTPUT TRISTATE ;
    USE SIGNAL ;
    PORT
      LAYER met2 ;
        RECT 284.830 0.000 285.110 4.000 ;
    END
  END la_data_out[8]
  PIN la_data_out[90]
    DIRECTION OUTPUT TRISTATE ;
    USE SIGNAL ;
    PORT
      LAYER met2 ;
        RECT 623.390 1496.000 623.670 1500.000 ;
    END
  END la_data_out[90]
  PIN la_data_out[91]
    DIRECTION OUTPUT TRISTATE ;
    USE SIGNAL ;
    PORT
      LAYER met2 ;
        RECT 646.390 1496.000 646.670 1500.000 ;
    END
  END la_data_out[91]
  PIN la_data_out[92]
    DIRECTION OUTPUT TRISTATE ;
    USE SIGNAL ;
    PORT
      LAYER met2 ;
        RECT 669.390 1496.000 669.670 1500.000 ;
    END
  END la_data_out[92]
  PIN la_data_out[93]
    DIRECTION OUTPUT TRISTATE ;
    USE SIGNAL ;
    PORT
      LAYER met2 ;
        RECT 692.390 1496.000 692.670 1500.000 ;
    END
  END la_data_out[93]
  PIN la_data_out[94]
    DIRECTION OUTPUT TRISTATE ;
    USE SIGNAL ;
    PORT
      LAYER met2 ;
        RECT 715.390 1496.000 715.670 1500.000 ;
    END
  END la_data_out[94]
  PIN la_data_out[95]
    DIRECTION OUTPUT TRISTATE ;
    USE SIGNAL ;
    PORT
      LAYER met2 ;
        RECT 738.390 1496.000 738.670 1500.000 ;
    END
  END la_data_out[95]
  PIN la_data_out[96]
    DIRECTION OUTPUT TRISTATE ;
    USE SIGNAL ;
    PORT
      LAYER met2 ;
        RECT 761.390 1496.000 761.670 1500.000 ;
    END
  END la_data_out[96]
  PIN la_data_out[97]
    DIRECTION OUTPUT TRISTATE ;
    USE SIGNAL ;
    PORT
      LAYER met2 ;
        RECT 784.390 1496.000 784.670 1500.000 ;
    END
  END la_data_out[97]
  PIN la_data_out[98]
    DIRECTION OUTPUT TRISTATE ;
    USE SIGNAL ;
    PORT
      LAYER met2 ;
        RECT 807.390 1496.000 807.670 1500.000 ;
    END
  END la_data_out[98]
  PIN la_data_out[99]
    DIRECTION OUTPUT TRISTATE ;
    USE SIGNAL ;
    PORT
      LAYER met2 ;
        RECT 830.390 1496.000 830.670 1500.000 ;
    END
  END la_data_out[99]
  PIN la_data_out[9]
    DIRECTION OUTPUT TRISTATE ;
    USE SIGNAL ;
    PORT
      LAYER met2 ;
        RECT 306.450 0.000 306.730 4.000 ;
    END
  END la_data_out[9]
  PIN rst_n
    DIRECTION INPUT ;
    USE SIGNAL ;
    PORT
      LAYER met3 ;
        RECT 1496.000 161.880 1500.000 162.480 ;
    END
  END rst_n
  PIN vccd1
    DIRECTION INOUT ;
    USE POWER ;
    PORT
      LAYER met4 ;
        RECT 21.040 10.640 22.640 1488.080 ;
    END
    PORT
      LAYER met4 ;
        RECT 174.640 10.640 176.240 90.020 ;
    END
    PORT
      LAYER met4 ;
        RECT 174.640 526.520 176.240 690.020 ;
    END
    PORT
      LAYER met4 ;
        RECT 174.640 1126.520 176.240 1488.080 ;
    END
    PORT
      LAYER met4 ;
        RECT 328.240 10.640 329.840 89.400 ;
    END
    PORT
      LAYER met4 ;
        RECT 328.240 526.520 329.840 689.400 ;
    END
    PORT
      LAYER met4 ;
        RECT 328.240 1126.520 329.840 1488.080 ;
    END
    PORT
      LAYER met4 ;
        RECT 481.840 10.640 483.440 90.020 ;
    END
    PORT
      LAYER met4 ;
        RECT 481.840 526.520 483.440 690.020 ;
    END
    PORT
      LAYER met4 ;
        RECT 481.840 1126.520 483.440 1488.080 ;
    END
    PORT
      LAYER met4 ;
        RECT 635.440 10.640 637.040 90.020 ;
    END
    PORT
      LAYER met4 ;
        RECT 635.440 526.520 637.040 690.020 ;
    END
    PORT
      LAYER met4 ;
        RECT 635.440 1126.520 637.040 1488.080 ;
    END
    PORT
      LAYER met4 ;
        RECT 789.040 10.640 790.640 90.020 ;
    END
    PORT
      LAYER met4 ;
        RECT 789.040 526.520 790.640 690.020 ;
    END
    PORT
      LAYER met4 ;
        RECT 789.040 1126.520 790.640 1488.080 ;
    END
    PORT
      LAYER met4 ;
        RECT 942.640 10.640 944.240 1488.080 ;
    END
    PORT
      LAYER met4 ;
        RECT 1096.240 10.640 1097.840 1488.080 ;
    END
    PORT
      LAYER met4 ;
        RECT 1249.840 10.640 1251.440 1488.080 ;
    END
    PORT
      LAYER met4 ;
        RECT 1403.440 10.640 1405.040 1488.080 ;
    END
    PORT
      LAYER met5 ;
        RECT 5.280 26.730 1494.320 28.330 ;
    END
    PORT
      LAYER met5 ;
        RECT 5.280 179.910 1494.320 181.510 ;
    END
    PORT
      LAYER met5 ;
        RECT 5.280 333.090 1494.320 334.690 ;
    END
    PORT
      LAYER met5 ;
        RECT 5.280 486.270 1494.320 487.870 ;
    END
    PORT
      LAYER met5 ;
        RECT 5.280 639.450 1494.320 641.050 ;
    END
    PORT
      LAYER met5 ;
        RECT 5.280 792.630 1494.320 794.230 ;
    END
    PORT
      LAYER met5 ;
        RECT 5.280 945.810 1494.320 947.410 ;
    END
    PORT
      LAYER met5 ;
        RECT 5.280 1098.990 1494.320 1100.590 ;
    END
    PORT
      LAYER met5 ;
        RECT 5.280 1252.170 1494.320 1253.770 ;
    END
    PORT
      LAYER met5 ;
        RECT 5.280 1405.350 1494.320 1406.950 ;
    END
  END vccd1
  PIN vccd2
    DIRECTION INOUT ;
    USE POWER ;
    PORT
      LAYER met4 ;
        RECT 27.640 10.640 29.240 1488.080 ;
    END
    PORT
      LAYER met4 ;
        RECT 181.240 1126.520 182.840 1488.080 ;
    END
    PORT
      LAYER met4 ;
        RECT 334.840 1126.520 336.440 1488.080 ;
    END
    PORT
      LAYER met4 ;
        RECT 488.440 1126.520 490.040 1488.080 ;
    END
    PORT
      LAYER met4 ;
        RECT 642.040 1126.520 643.640 1488.080 ;
    END
    PORT
      LAYER met4 ;
        RECT 795.640 10.640 797.240 1488.080 ;
    END
    PORT
      LAYER met4 ;
        RECT 949.240 10.640 950.840 1488.080 ;
    END
    PORT
      LAYER met4 ;
        RECT 1102.840 10.640 1104.440 1488.080 ;
    END
    PORT
      LAYER met4 ;
        RECT 1256.440 10.640 1258.040 1488.080 ;
    END
    PORT
      LAYER met4 ;
        RECT 1410.040 10.640 1411.640 1488.080 ;
    END
    PORT
      LAYER met5 ;
        RECT 5.280 33.330 1494.320 34.930 ;
    END
    PORT
      LAYER met5 ;
        RECT 5.280 186.510 1494.320 188.110 ;
    END
    PORT
      LAYER met5 ;
        RECT 5.280 339.690 1494.320 341.290 ;
    END
    PORT
      LAYER met5 ;
        RECT 5.280 492.870 1494.320 494.470 ;
    END
    PORT
      LAYER met5 ;
        RECT 5.280 646.050 1494.320 647.650 ;
    END
    PORT
      LAYER met5 ;
        RECT 5.280 799.230 1494.320 800.830 ;
    END
    PORT
      LAYER met5 ;
        RECT 5.280 952.410 1494.320 954.010 ;
    END
    PORT
      LAYER met5 ;
        RECT 5.280 1105.590 1494.320 1107.190 ;
    END
    PORT
      LAYER met5 ;
        RECT 5.280 1258.770 1494.320 1260.370 ;
    END
    PORT
      LAYER met5 ;
        RECT 5.280 1411.950 1494.320 1413.550 ;
    END
  END vccd2
  PIN vdda1
    DIRECTION INOUT ;
    USE POWER ;
    PORT
      LAYER met4 ;
        RECT 34.240 10.640 35.840 1488.080 ;
    END
    PORT
      LAYER met4 ;
        RECT 187.840 1126.520 189.440 1488.080 ;
    END
    PORT
      LAYER met4 ;
        RECT 341.440 1127.140 343.040 1488.080 ;
    END
    PORT
      LAYER met4 ;
        RECT 495.040 1126.520 496.640 1488.080 ;
    END
    PORT
      LAYER met4 ;
        RECT 648.640 1126.520 650.240 1488.080 ;
    END
    PORT
      LAYER met4 ;
        RECT 802.240 10.640 803.840 1488.080 ;
    END
    PORT
      LAYER met4 ;
        RECT 955.840 10.640 957.440 1488.080 ;
    END
    PORT
      LAYER met4 ;
        RECT 1109.440 10.640 1111.040 1488.080 ;
    END
    PORT
      LAYER met4 ;
        RECT 1263.040 10.640 1264.640 1488.080 ;
    END
    PORT
      LAYER met4 ;
        RECT 1416.640 10.640 1418.240 1488.080 ;
    END
    PORT
      LAYER met5 ;
        RECT 5.280 39.930 1494.320 41.530 ;
    END
    PORT
      LAYER met5 ;
        RECT 5.280 193.110 1494.320 194.710 ;
    END
    PORT
      LAYER met5 ;
        RECT 5.280 346.290 1494.320 347.890 ;
    END
    PORT
      LAYER met5 ;
        RECT 5.280 499.470 1494.320 501.070 ;
    END
    PORT
      LAYER met5 ;
        RECT 5.280 652.650 1494.320 654.250 ;
    END
    PORT
      LAYER met5 ;
        RECT 5.280 805.830 1494.320 807.430 ;
    END
    PORT
      LAYER met5 ;
        RECT 5.280 959.010 1494.320 960.610 ;
    END
    PORT
      LAYER met5 ;
        RECT 5.280 1112.190 1494.320 1113.790 ;
    END
    PORT
      LAYER met5 ;
        RECT 5.280 1265.370 1494.320 1266.970 ;
    END
    PORT
      LAYER met5 ;
        RECT 5.280 1418.550 1494.320 1420.150 ;
    END
  END vdda1
  PIN vdda2
    DIRECTION INOUT ;
    USE POWER ;
    PORT
      LAYER met4 ;
        RECT 40.840 10.640 42.440 1488.080 ;
    END
    PORT
      LAYER met4 ;
        RECT 194.440 1126.520 196.040 1488.080 ;
    END
    PORT
      LAYER met4 ;
        RECT 348.040 1126.520 349.640 1488.080 ;
    END
    PORT
      LAYER met4 ;
        RECT 501.640 1126.520 503.240 1488.080 ;
    END
    PORT
      LAYER met4 ;
        RECT 655.240 1126.520 656.840 1488.080 ;
    END
    PORT
      LAYER met4 ;
        RECT 808.840 10.640 810.440 1488.080 ;
    END
    PORT
      LAYER met4 ;
        RECT 962.440 10.640 964.040 1488.080 ;
    END
    PORT
      LAYER met4 ;
        RECT 1116.040 10.640 1117.640 1488.080 ;
    END
    PORT
      LAYER met4 ;
        RECT 1269.640 10.640 1271.240 1488.080 ;
    END
    PORT
      LAYER met4 ;
        RECT 1423.240 10.640 1424.840 1488.080 ;
    END
    PORT
      LAYER met5 ;
        RECT 5.280 46.530 1494.320 48.130 ;
    END
    PORT
      LAYER met5 ;
        RECT 5.280 199.710 1494.320 201.310 ;
    END
    PORT
      LAYER met5 ;
        RECT 5.280 352.890 1494.320 354.490 ;
    END
    PORT
      LAYER met5 ;
        RECT 5.280 506.070 1494.320 507.670 ;
    END
    PORT
      LAYER met5 ;
        RECT 5.280 659.250 1494.320 660.850 ;
    END
    PORT
      LAYER met5 ;
        RECT 5.280 812.430 1494.320 814.030 ;
    END
    PORT
      LAYER met5 ;
        RECT 5.280 965.610 1494.320 967.210 ;
    END
    PORT
      LAYER met5 ;
        RECT 5.280 1118.790 1494.320 1120.390 ;
    END
    PORT
      LAYER met5 ;
        RECT 5.280 1271.970 1494.320 1273.570 ;
    END
    PORT
      LAYER met5 ;
        RECT 5.280 1425.150 1494.320 1426.750 ;
    END
  END vdda2
  PIN vssa1
    DIRECTION INOUT ;
    USE GROUND ;
    PORT
      LAYER met4 ;
        RECT 37.540 10.640 39.140 1488.080 ;
    END
    PORT
      LAYER met4 ;
        RECT 191.140 1126.520 192.740 1488.080 ;
    END
    PORT
      LAYER met4 ;
        RECT 344.740 1126.520 346.340 1488.080 ;
    END
    PORT
      LAYER met4 ;
        RECT 498.340 1126.520 499.940 1488.080 ;
    END
    PORT
      LAYER met4 ;
        RECT 651.940 1126.520 653.540 1488.080 ;
    END
    PORT
      LAYER met4 ;
        RECT 805.540 10.640 807.140 1488.080 ;
    END
    PORT
      LAYER met4 ;
        RECT 959.140 10.640 960.740 1488.080 ;
    END
    PORT
      LAYER met4 ;
        RECT 1112.740 10.640 1114.340 1488.080 ;
    END
    PORT
      LAYER met4 ;
        RECT 1266.340 10.640 1267.940 1488.080 ;
    END
    PORT
      LAYER met4 ;
        RECT 1419.940 10.640 1421.540 1488.080 ;
    END
    PORT
      LAYER met5 ;
        RECT 5.280 43.230 1494.320 44.830 ;
    END
    PORT
      LAYER met5 ;
        RECT 5.280 196.410 1494.320 198.010 ;
    END
    PORT
      LAYER met5 ;
        RECT 5.280 349.590 1494.320 351.190 ;
    END
    PORT
      LAYER met5 ;
        RECT 5.280 502.770 1494.320 504.370 ;
    END
    PORT
      LAYER met5 ;
        RECT 5.280 655.950 1494.320 657.550 ;
    END
    PORT
      LAYER met5 ;
        RECT 5.280 809.130 1494.320 810.730 ;
    END
    PORT
      LAYER met5 ;
        RECT 5.280 962.310 1494.320 963.910 ;
    END
    PORT
      LAYER met5 ;
        RECT 5.280 1115.490 1494.320 1117.090 ;
    END
    PORT
      LAYER met5 ;
        RECT 5.280 1268.670 1494.320 1270.270 ;
    END
    PORT
      LAYER met5 ;
        RECT 5.280 1421.850 1494.320 1423.450 ;
    END
  END vssa1
  PIN vssa2
    DIRECTION INOUT ;
    USE GROUND ;
    PORT
      LAYER met4 ;
        RECT 44.140 10.640 45.740 1488.080 ;
    END
    PORT
      LAYER met4 ;
        RECT 197.740 1126.520 199.340 1488.080 ;
    END
    PORT
      LAYER met4 ;
        RECT 351.340 1126.520 352.940 1488.080 ;
    END
    PORT
      LAYER met4 ;
        RECT 504.940 1127.140 506.540 1488.080 ;
    END
    PORT
      LAYER met4 ;
        RECT 658.540 1126.520 660.140 1488.080 ;
    END
    PORT
      LAYER met4 ;
        RECT 812.140 10.640 813.740 1488.080 ;
    END
    PORT
      LAYER met4 ;
        RECT 965.740 10.640 967.340 1488.080 ;
    END
    PORT
      LAYER met4 ;
        RECT 1119.340 10.640 1120.940 1488.080 ;
    END
    PORT
      LAYER met4 ;
        RECT 1272.940 10.640 1274.540 1488.080 ;
    END
    PORT
      LAYER met4 ;
        RECT 1426.540 10.640 1428.140 1488.080 ;
    END
    PORT
      LAYER met5 ;
        RECT 5.280 49.830 1494.320 51.430 ;
    END
    PORT
      LAYER met5 ;
        RECT 5.280 203.010 1494.320 204.610 ;
    END
    PORT
      LAYER met5 ;
        RECT 5.280 356.190 1494.320 357.790 ;
    END
    PORT
      LAYER met5 ;
        RECT 5.280 509.370 1494.320 510.970 ;
    END
    PORT
      LAYER met5 ;
        RECT 5.280 662.550 1494.320 664.150 ;
    END
    PORT
      LAYER met5 ;
        RECT 5.280 815.730 1494.320 817.330 ;
    END
    PORT
      LAYER met5 ;
        RECT 5.280 968.910 1494.320 970.510 ;
    END
    PORT
      LAYER met5 ;
        RECT 5.280 1122.090 1494.320 1123.690 ;
    END
    PORT
      LAYER met5 ;
        RECT 5.280 1275.270 1494.320 1276.870 ;
    END
    PORT
      LAYER met5 ;
        RECT 5.280 1428.450 1494.320 1430.050 ;
    END
  END vssa2
  PIN vssd1
    DIRECTION INOUT ;
    USE GROUND ;
    PORT
      LAYER met4 ;
        RECT 24.340 10.640 25.940 1488.080 ;
    END
    PORT
      LAYER met4 ;
        RECT 177.940 10.640 179.540 90.020 ;
    END
    PORT
      LAYER met4 ;
        RECT 177.940 526.520 179.540 690.020 ;
    END
    PORT
      LAYER met4 ;
        RECT 177.940 1126.520 179.540 1488.080 ;
    END
    PORT
      LAYER met4 ;
        RECT 331.540 10.640 333.140 89.400 ;
    END
    PORT
      LAYER met4 ;
        RECT 331.540 526.520 333.140 689.400 ;
    END
    PORT
      LAYER met4 ;
        RECT 331.540 1126.520 333.140 1488.080 ;
    END
    PORT
      LAYER met4 ;
        RECT 485.140 10.640 486.740 90.020 ;
    END
    PORT
      LAYER met4 ;
        RECT 485.140 526.520 486.740 690.020 ;
    END
    PORT
      LAYER met4 ;
        RECT 485.140 1126.520 486.740 1488.080 ;
    END
    PORT
      LAYER met4 ;
        RECT 638.740 10.640 640.340 90.020 ;
    END
    PORT
      LAYER met4 ;
        RECT 638.740 526.520 640.340 690.020 ;
    END
    PORT
      LAYER met4 ;
        RECT 638.740 1126.520 640.340 1488.080 ;
    END
    PORT
      LAYER met4 ;
        RECT 792.340 10.640 793.940 90.020 ;
    END
    PORT
      LAYER met4 ;
        RECT 792.340 526.520 793.940 690.020 ;
    END
    PORT
      LAYER met4 ;
        RECT 792.340 1126.520 793.940 1488.080 ;
    END
    PORT
      LAYER met4 ;
        RECT 945.940 10.640 947.540 1488.080 ;
    END
    PORT
      LAYER met4 ;
        RECT 1099.540 10.640 1101.140 1488.080 ;
    END
    PORT
      LAYER met4 ;
        RECT 1253.140 10.640 1254.740 1488.080 ;
    END
    PORT
      LAYER met4 ;
        RECT 1406.740 10.640 1408.340 1488.080 ;
    END
    PORT
      LAYER met5 ;
        RECT 5.280 30.030 1494.320 31.630 ;
    END
    PORT
      LAYER met5 ;
        RECT 5.280 183.210 1494.320 184.810 ;
    END
    PORT
      LAYER met5 ;
        RECT 5.280 336.390 1494.320 337.990 ;
    END
    PORT
      LAYER met5 ;
        RECT 5.280 489.570 1494.320 491.170 ;
    END
    PORT
      LAYER met5 ;
        RECT 5.280 642.750 1494.320 644.350 ;
    END
    PORT
      LAYER met5 ;
        RECT 5.280 795.930 1494.320 797.530 ;
    END
    PORT
      LAYER met5 ;
        RECT 5.280 949.110 1494.320 950.710 ;
    END
    PORT
      LAYER met5 ;
        RECT 5.280 1102.290 1494.320 1103.890 ;
    END
    PORT
      LAYER met5 ;
        RECT 5.280 1255.470 1494.320 1257.070 ;
    END
    PORT
      LAYER met5 ;
        RECT 5.280 1408.650 1494.320 1410.250 ;
    END
  END vssd1
  PIN vssd2
    DIRECTION INOUT ;
    USE GROUND ;
    PORT
      LAYER met4 ;
        RECT 30.940 10.640 32.540 1488.080 ;
    END
    PORT
      LAYER met4 ;
        RECT 184.540 1126.520 186.140 1488.080 ;
    END
    PORT
      LAYER met4 ;
        RECT 338.140 1126.520 339.740 1488.080 ;
    END
    PORT
      LAYER met4 ;
        RECT 491.740 1127.140 493.340 1488.080 ;
    END
    PORT
      LAYER met4 ;
        RECT 645.340 1126.520 646.940 1488.080 ;
    END
    PORT
      LAYER met4 ;
        RECT 798.940 10.640 800.540 1488.080 ;
    END
    PORT
      LAYER met4 ;
        RECT 952.540 10.640 954.140 1488.080 ;
    END
    PORT
      LAYER met4 ;
        RECT 1106.140 10.640 1107.740 1488.080 ;
    END
    PORT
      LAYER met4 ;
        RECT 1259.740 10.640 1261.340 1488.080 ;
    END
    PORT
      LAYER met4 ;
        RECT 1413.340 10.640 1414.940 1488.080 ;
    END
    PORT
      LAYER met5 ;
        RECT 5.280 36.630 1494.320 38.230 ;
    END
    PORT
      LAYER met5 ;
        RECT 5.280 189.810 1494.320 191.410 ;
    END
    PORT
      LAYER met5 ;
        RECT 5.280 342.990 1494.320 344.590 ;
    END
    PORT
      LAYER met5 ;
        RECT 5.280 496.170 1494.320 497.770 ;
    END
    PORT
      LAYER met5 ;
        RECT 5.280 649.350 1494.320 650.950 ;
    END
    PORT
      LAYER met5 ;
        RECT 5.280 802.530 1494.320 804.130 ;
    END
    PORT
      LAYER met5 ;
        RECT 5.280 955.710 1494.320 957.310 ;
    END
    PORT
      LAYER met5 ;
        RECT 5.280 1108.890 1494.320 1110.490 ;
    END
    PORT
      LAYER met5 ;
        RECT 5.280 1262.070 1494.320 1263.670 ;
    END
    PORT
      LAYER met5 ;
        RECT 5.280 1415.250 1494.320 1416.850 ;
    END
  END vssd2
  PIN wb_clk_i
    DIRECTION INPUT ;
    USE SIGNAL ;
    ANTENNAGATEAREA 0.990000 ;
    PORT
      LAYER met3 ;
        RECT 1496.000 174.120 1500.000 174.720 ;
    END
  END wb_clk_i
  PIN wb_rst_i
    DIRECTION INPUT ;
    USE SIGNAL ;
    ANTENNAGATEAREA 0.196500 ;
    PORT
      LAYER met2 ;
        RECT 25.390 0.000 25.670 4.000 ;
    END
  END wb_rst_i
  PIN wbs_ack_o
    DIRECTION OUTPUT TRISTATE ;
    USE SIGNAL ;
    ANTENNADIFFAREA 0.445500 ;
    PORT
      LAYER met3 ;
        RECT 1496.000 186.360 1500.000 186.960 ;
    END
  END wbs_ack_o
  PIN wbs_adr_i[0]
    DIRECTION INPUT ;
    USE SIGNAL ;
    ANTENNAGATEAREA 0.196500 ;
    PORT
      LAYER met3 ;
        RECT 1496.000 235.320 1500.000 235.920 ;
    END
  END wbs_adr_i[0]
  PIN wbs_adr_i[10]
    DIRECTION INPUT ;
    USE SIGNAL ;
    ANTENNAGATEAREA 0.852000 ;
    PORT
      LAYER met3 ;
        RECT 1496.000 357.720 1500.000 358.320 ;
    END
  END wbs_adr_i[10]
  PIN wbs_adr_i[11]
    DIRECTION INPUT ;
    USE SIGNAL ;
    ANTENNAGATEAREA 0.196500 ;
    PORT
      LAYER met3 ;
        RECT 1496.000 369.960 1500.000 370.560 ;
    END
  END wbs_adr_i[11]
  PIN wbs_adr_i[12]
    DIRECTION INPUT ;
    USE SIGNAL ;
    ANTENNAGATEAREA 0.196500 ;
    PORT
      LAYER met3 ;
        RECT 1496.000 382.200 1500.000 382.800 ;
    END
  END wbs_adr_i[12]
  PIN wbs_adr_i[13]
    DIRECTION INPUT ;
    USE SIGNAL ;
    ANTENNAGATEAREA 0.213000 ;
    PORT
      LAYER met3 ;
        RECT 1496.000 394.440 1500.000 395.040 ;
    END
  END wbs_adr_i[13]
  PIN wbs_adr_i[14]
    DIRECTION INPUT ;
    USE SIGNAL ;
    ANTENNAGATEAREA 0.196500 ;
    PORT
      LAYER met3 ;
        RECT 1496.000 406.680 1500.000 407.280 ;
    END
  END wbs_adr_i[14]
  PIN wbs_adr_i[15]
    DIRECTION INPUT ;
    USE SIGNAL ;
    ANTENNAGATEAREA 0.126000 ;
    PORT
      LAYER met3 ;
        RECT 1496.000 418.920 1500.000 419.520 ;
    END
  END wbs_adr_i[15]
  PIN wbs_adr_i[16]
    DIRECTION INPUT ;
    USE SIGNAL ;
    ANTENNAGATEAREA 0.126000 ;
    PORT
      LAYER met3 ;
        RECT 1496.000 431.160 1500.000 431.760 ;
    END
  END wbs_adr_i[16]
  PIN wbs_adr_i[17]
    DIRECTION INPUT ;
    USE SIGNAL ;
    ANTENNAGATEAREA 0.196500 ;
    PORT
      LAYER met3 ;
        RECT 1496.000 443.400 1500.000 444.000 ;
    END
  END wbs_adr_i[17]
  PIN wbs_adr_i[18]
    DIRECTION INPUT ;
    USE SIGNAL ;
    ANTENNAGATEAREA 0.196500 ;
    PORT
      LAYER met3 ;
        RECT 1496.000 455.640 1500.000 456.240 ;
    END
  END wbs_adr_i[18]
  PIN wbs_adr_i[19]
    DIRECTION INPUT ;
    USE SIGNAL ;
    ANTENNAGATEAREA 0.196500 ;
    PORT
      LAYER met3 ;
        RECT 1496.000 467.880 1500.000 468.480 ;
    END
  END wbs_adr_i[19]
  PIN wbs_adr_i[1]
    DIRECTION INPUT ;
    USE SIGNAL ;
    ANTENNAGATEAREA 0.196500 ;
    PORT
      LAYER met3 ;
        RECT 1496.000 247.560 1500.000 248.160 ;
    END
  END wbs_adr_i[1]
  PIN wbs_adr_i[20]
    DIRECTION INPUT ;
    USE SIGNAL ;
    ANTENNAGATEAREA 0.196500 ;
    PORT
      LAYER met3 ;
        RECT 1496.000 480.120 1500.000 480.720 ;
    END
  END wbs_adr_i[20]
  PIN wbs_adr_i[21]
    DIRECTION INPUT ;
    USE SIGNAL ;
    ANTENNAGATEAREA 0.196500 ;
    PORT
      LAYER met3 ;
        RECT 1496.000 492.360 1500.000 492.960 ;
    END
  END wbs_adr_i[21]
  PIN wbs_adr_i[22]
    DIRECTION INPUT ;
    USE SIGNAL ;
    ANTENNAGATEAREA 0.196500 ;
    PORT
      LAYER met3 ;
        RECT 1496.000 504.600 1500.000 505.200 ;
    END
  END wbs_adr_i[22]
  PIN wbs_adr_i[23]
    DIRECTION INPUT ;
    USE SIGNAL ;
    ANTENNAGATEAREA 0.196500 ;
    PORT
      LAYER met3 ;
        RECT 1496.000 516.840 1500.000 517.440 ;
    END
  END wbs_adr_i[23]
  PIN wbs_adr_i[24]
    DIRECTION INPUT ;
    USE SIGNAL ;
    ANTENNAGATEAREA 0.196500 ;
    PORT
      LAYER met3 ;
        RECT 1496.000 529.080 1500.000 529.680 ;
    END
  END wbs_adr_i[24]
  PIN wbs_adr_i[25]
    DIRECTION INPUT ;
    USE SIGNAL ;
    ANTENNAGATEAREA 0.196500 ;
    PORT
      LAYER met3 ;
        RECT 1496.000 541.320 1500.000 541.920 ;
    END
  END wbs_adr_i[25]
  PIN wbs_adr_i[26]
    DIRECTION INPUT ;
    USE SIGNAL ;
    ANTENNAGATEAREA 0.196500 ;
    PORT
      LAYER met3 ;
        RECT 1496.000 553.560 1500.000 554.160 ;
    END
  END wbs_adr_i[26]
  PIN wbs_adr_i[27]
    DIRECTION INPUT ;
    USE SIGNAL ;
    ANTENNAGATEAREA 0.196500 ;
    PORT
      LAYER met3 ;
        RECT 1496.000 565.800 1500.000 566.400 ;
    END
  END wbs_adr_i[27]
  PIN wbs_adr_i[28]
    DIRECTION INPUT ;
    USE SIGNAL ;
    ANTENNAGATEAREA 0.196500 ;
    PORT
      LAYER met3 ;
        RECT 1496.000 578.040 1500.000 578.640 ;
    END
  END wbs_adr_i[28]
  PIN wbs_adr_i[29]
    DIRECTION INPUT ;
    USE SIGNAL ;
    ANTENNAGATEAREA 0.196500 ;
    PORT
      LAYER met3 ;
        RECT 1496.000 590.280 1500.000 590.880 ;
    END
  END wbs_adr_i[29]
  PIN wbs_adr_i[2]
    DIRECTION INPUT ;
    USE SIGNAL ;
    ANTENNAGATEAREA 0.742500 ;
    PORT
      LAYER met3 ;
        RECT 1496.000 259.800 1500.000 260.400 ;
    END
  END wbs_adr_i[2]
  PIN wbs_adr_i[30]
    DIRECTION INPUT ;
    USE SIGNAL ;
    ANTENNAGATEAREA 0.196500 ;
    PORT
      LAYER met3 ;
        RECT 1496.000 602.520 1500.000 603.120 ;
    END
  END wbs_adr_i[30]
  PIN wbs_adr_i[31]
    DIRECTION INPUT ;
    USE SIGNAL ;
    ANTENNAGATEAREA 0.196500 ;
    PORT
      LAYER met3 ;
        RECT 1496.000 614.760 1500.000 615.360 ;
    END
  END wbs_adr_i[31]
  PIN wbs_adr_i[3]
    DIRECTION INPUT ;
    USE SIGNAL ;
    ANTENNAGATEAREA 0.852000 ;
    PORT
      LAYER met3 ;
        RECT 1496.000 272.040 1500.000 272.640 ;
    END
  END wbs_adr_i[3]
  PIN wbs_adr_i[4]
    DIRECTION INPUT ;
    USE SIGNAL ;
    ANTENNAGATEAREA 0.852000 ;
    PORT
      LAYER met3 ;
        RECT 1496.000 284.280 1500.000 284.880 ;
    END
  END wbs_adr_i[4]
  PIN wbs_adr_i[5]
    DIRECTION INPUT ;
    USE SIGNAL ;
    ANTENNAGATEAREA 0.852000 ;
    PORT
      LAYER met3 ;
        RECT 1496.000 296.520 1500.000 297.120 ;
    END
  END wbs_adr_i[5]
  PIN wbs_adr_i[6]
    DIRECTION INPUT ;
    USE SIGNAL ;
    ANTENNAGATEAREA 0.852000 ;
    PORT
      LAYER met3 ;
        RECT 1496.000 308.760 1500.000 309.360 ;
    END
  END wbs_adr_i[6]
  PIN wbs_adr_i[7]
    DIRECTION INPUT ;
    USE SIGNAL ;
    ANTENNAGATEAREA 0.852000 ;
    PORT
      LAYER met3 ;
        RECT 1496.000 321.000 1500.000 321.600 ;
    END
  END wbs_adr_i[7]
  PIN wbs_adr_i[8]
    DIRECTION INPUT ;
    USE SIGNAL ;
    ANTENNAGATEAREA 0.852000 ;
    PORT
      LAYER met3 ;
        RECT 1496.000 333.240 1500.000 333.840 ;
    END
  END wbs_adr_i[8]
  PIN wbs_adr_i[9]
    DIRECTION INPUT ;
    USE SIGNAL ;
    ANTENNAGATEAREA 0.852000 ;
    PORT
      LAYER met3 ;
        RECT 1496.000 345.480 1500.000 346.080 ;
    END
  END wbs_adr_i[9]
  PIN wbs_cyc_i
    DIRECTION INPUT ;
    USE SIGNAL ;
    ANTENNAGATEAREA 0.742500 ;
    PORT
      LAYER met2 ;
        RECT 47.010 0.000 47.290 4.000 ;
    END
  END wbs_cyc_i
  PIN wbs_dat_i[0]
    DIRECTION INPUT ;
    USE SIGNAL ;
    ANTENNAGATEAREA 0.852000 ;
    PORT
      LAYER met3 ;
        RECT 1496.000 627.000 1500.000 627.600 ;
    END
  END wbs_dat_i[0]
  PIN wbs_dat_i[10]
    DIRECTION INPUT ;
    USE SIGNAL ;
    ANTENNAGATEAREA 0.742500 ;
    PORT
      LAYER met3 ;
        RECT 1496.000 749.400 1500.000 750.000 ;
    END
  END wbs_dat_i[10]
  PIN wbs_dat_i[11]
    DIRECTION INPUT ;
    USE SIGNAL ;
    ANTENNAGATEAREA 0.742500 ;
    PORT
      LAYER met3 ;
        RECT 1496.000 761.640 1500.000 762.240 ;
    END
  END wbs_dat_i[11]
  PIN wbs_dat_i[12]
    DIRECTION INPUT ;
    USE SIGNAL ;
    ANTENNAGATEAREA 0.742500 ;
    PORT
      LAYER met3 ;
        RECT 1496.000 773.880 1500.000 774.480 ;
    END
  END wbs_dat_i[12]
  PIN wbs_dat_i[13]
    DIRECTION INPUT ;
    USE SIGNAL ;
    ANTENNAGATEAREA 0.742500 ;
    PORT
      LAYER met3 ;
        RECT 1496.000 786.120 1500.000 786.720 ;
    END
  END wbs_dat_i[13]
  PIN wbs_dat_i[14]
    DIRECTION INPUT ;
    USE SIGNAL ;
    ANTENNAGATEAREA 0.495000 ;
    PORT
      LAYER met3 ;
        RECT 1496.000 798.360 1500.000 798.960 ;
    END
  END wbs_dat_i[14]
  PIN wbs_dat_i[15]
    DIRECTION INPUT ;
    USE SIGNAL ;
    ANTENNAGATEAREA 0.495000 ;
    PORT
      LAYER met3 ;
        RECT 1496.000 810.600 1500.000 811.200 ;
    END
  END wbs_dat_i[15]
  PIN wbs_dat_i[16]
    DIRECTION INPUT ;
    USE SIGNAL ;
    ANTENNAGATEAREA 0.495000 ;
    PORT
      LAYER met3 ;
        RECT 1496.000 822.840 1500.000 823.440 ;
    END
  END wbs_dat_i[16]
  PIN wbs_dat_i[17]
    DIRECTION INPUT ;
    USE SIGNAL ;
    ANTENNAGATEAREA 0.495000 ;
    PORT
      LAYER met3 ;
        RECT 1496.000 835.080 1500.000 835.680 ;
    END
  END wbs_dat_i[17]
  PIN wbs_dat_i[18]
    DIRECTION INPUT ;
    USE SIGNAL ;
    ANTENNAGATEAREA 0.495000 ;
    PORT
      LAYER met3 ;
        RECT 1496.000 847.320 1500.000 847.920 ;
    END
  END wbs_dat_i[18]
  PIN wbs_dat_i[19]
    DIRECTION INPUT ;
    USE SIGNAL ;
    ANTENNAGATEAREA 0.495000 ;
    PORT
      LAYER met3 ;
        RECT 1496.000 859.560 1500.000 860.160 ;
    END
  END wbs_dat_i[19]
  PIN wbs_dat_i[1]
    DIRECTION INPUT ;
    USE SIGNAL ;
    ANTENNAGATEAREA 0.742500 ;
    PORT
      LAYER met3 ;
        RECT 1496.000 639.240 1500.000 639.840 ;
    END
  END wbs_dat_i[1]
  PIN wbs_dat_i[20]
    DIRECTION INPUT ;
    USE SIGNAL ;
    ANTENNAGATEAREA 0.495000 ;
    PORT
      LAYER met3 ;
        RECT 1496.000 871.800 1500.000 872.400 ;
    END
  END wbs_dat_i[20]
  PIN wbs_dat_i[21]
    DIRECTION INPUT ;
    USE SIGNAL ;
    ANTENNAGATEAREA 0.742500 ;
    PORT
      LAYER met3 ;
        RECT 1496.000 884.040 1500.000 884.640 ;
    END
  END wbs_dat_i[21]
  PIN wbs_dat_i[22]
    DIRECTION INPUT ;
    USE SIGNAL ;
    ANTENNAGATEAREA 0.742500 ;
    PORT
      LAYER met3 ;
        RECT 1496.000 896.280 1500.000 896.880 ;
    END
  END wbs_dat_i[22]
  PIN wbs_dat_i[23]
    DIRECTION INPUT ;
    USE SIGNAL ;
    ANTENNAGATEAREA 0.742500 ;
    PORT
      LAYER met3 ;
        RECT 1496.000 908.520 1500.000 909.120 ;
    END
  END wbs_dat_i[23]
  PIN wbs_dat_i[24]
    DIRECTION INPUT ;
    USE SIGNAL ;
    ANTENNAGATEAREA 0.495000 ;
    PORT
      LAYER met3 ;
        RECT 1496.000 920.760 1500.000 921.360 ;
    END
  END wbs_dat_i[24]
  PIN wbs_dat_i[25]
    DIRECTION INPUT ;
    USE SIGNAL ;
    ANTENNAGATEAREA 0.495000 ;
    PORT
      LAYER met3 ;
        RECT 1496.000 933.000 1500.000 933.600 ;
    END
  END wbs_dat_i[25]
  PIN wbs_dat_i[26]
    DIRECTION INPUT ;
    USE SIGNAL ;
    ANTENNAGATEAREA 0.742500 ;
    PORT
      LAYER met3 ;
        RECT 1496.000 945.240 1500.000 945.840 ;
    END
  END wbs_dat_i[26]
  PIN wbs_dat_i[27]
    DIRECTION INPUT ;
    USE SIGNAL ;
    ANTENNAGATEAREA 0.495000 ;
    PORT
      LAYER met3 ;
        RECT 1496.000 957.480 1500.000 958.080 ;
    END
  END wbs_dat_i[27]
  PIN wbs_dat_i[28]
    DIRECTION INPUT ;
    USE SIGNAL ;
    ANTENNAGATEAREA 0.495000 ;
    PORT
      LAYER met3 ;
        RECT 1496.000 969.720 1500.000 970.320 ;
    END
  END wbs_dat_i[28]
  PIN wbs_dat_i[29]
    DIRECTION INPUT ;
    USE SIGNAL ;
    ANTENNAGATEAREA 0.495000 ;
    PORT
      LAYER met3 ;
        RECT 1496.000 981.960 1500.000 982.560 ;
    END
  END wbs_dat_i[29]
  PIN wbs_dat_i[2]
    DIRECTION INPUT ;
    USE SIGNAL ;
    ANTENNAGATEAREA 0.742500 ;
    PORT
      LAYER met3 ;
        RECT 1496.000 651.480 1500.000 652.080 ;
    END
  END wbs_dat_i[2]
  PIN wbs_dat_i[30]
    DIRECTION INPUT ;
    USE SIGNAL ;
    ANTENNAGATEAREA 0.495000 ;
    PORT
      LAYER met3 ;
        RECT 1496.000 994.200 1500.000 994.800 ;
    END
  END wbs_dat_i[30]
  PIN wbs_dat_i[31]
    DIRECTION INPUT ;
    USE SIGNAL ;
    ANTENNAGATEAREA 0.495000 ;
    PORT
      LAYER met3 ;
        RECT 1496.000 1006.440 1500.000 1007.040 ;
    END
  END wbs_dat_i[31]
  PIN wbs_dat_i[3]
    DIRECTION INPUT ;
    USE SIGNAL ;
    ANTENNAGATEAREA 0.990000 ;
    PORT
      LAYER met3 ;
        RECT 1496.000 663.720 1500.000 664.320 ;
    END
  END wbs_dat_i[3]
  PIN wbs_dat_i[4]
    DIRECTION INPUT ;
    USE SIGNAL ;
    ANTENNAGATEAREA 0.742500 ;
    PORT
      LAYER met3 ;
        RECT 1496.000 675.960 1500.000 676.560 ;
    END
  END wbs_dat_i[4]
  PIN wbs_dat_i[5]
    DIRECTION INPUT ;
    USE SIGNAL ;
    ANTENNAGATEAREA 0.742500 ;
    PORT
      LAYER met3 ;
        RECT 1496.000 688.200 1500.000 688.800 ;
    END
  END wbs_dat_i[5]
  PIN wbs_dat_i[6]
    DIRECTION INPUT ;
    USE SIGNAL ;
    ANTENNAGATEAREA 0.742500 ;
    PORT
      LAYER met3 ;
        RECT 1496.000 700.440 1500.000 701.040 ;
    END
  END wbs_dat_i[6]
  PIN wbs_dat_i[7]
    DIRECTION INPUT ;
    USE SIGNAL ;
    ANTENNAGATEAREA 0.742500 ;
    PORT
      LAYER met3 ;
        RECT 1496.000 712.680 1500.000 713.280 ;
    END
  END wbs_dat_i[7]
  PIN wbs_dat_i[8]
    DIRECTION INPUT ;
    USE SIGNAL ;
    ANTENNAGATEAREA 0.742500 ;
    PORT
      LAYER met3 ;
        RECT 1496.000 724.920 1500.000 725.520 ;
    END
  END wbs_dat_i[8]
  PIN wbs_dat_i[9]
    DIRECTION INPUT ;
    USE SIGNAL ;
    ANTENNAGATEAREA 0.742500 ;
    PORT
      LAYER met3 ;
        RECT 1496.000 737.160 1500.000 737.760 ;
    END
  END wbs_dat_i[9]
  PIN wbs_dat_o[0]
    DIRECTION OUTPUT TRISTATE ;
    USE SIGNAL ;
    ANTENNADIFFAREA 0.795200 ;
    PORT
      LAYER met3 ;
        RECT 1496.000 1018.680 1500.000 1019.280 ;
    END
  END wbs_dat_o[0]
  PIN wbs_dat_o[10]
    DIRECTION OUTPUT TRISTATE ;
    USE SIGNAL ;
    ANTENNADIFFAREA 0.445500 ;
    PORT
      LAYER met3 ;
        RECT 1496.000 1141.080 1500.000 1141.680 ;
    END
  END wbs_dat_o[10]
  PIN wbs_dat_o[11]
    DIRECTION OUTPUT TRISTATE ;
    USE SIGNAL ;
    ANTENNADIFFAREA 0.445500 ;
    PORT
      LAYER met3 ;
        RECT 1496.000 1153.320 1500.000 1153.920 ;
    END
  END wbs_dat_o[11]
  PIN wbs_dat_o[12]
    DIRECTION OUTPUT TRISTATE ;
    USE SIGNAL ;
    ANTENNADIFFAREA 0.795200 ;
    PORT
      LAYER met3 ;
        RECT 1496.000 1165.560 1500.000 1166.160 ;
    END
  END wbs_dat_o[12]
  PIN wbs_dat_o[13]
    DIRECTION OUTPUT TRISTATE ;
    USE SIGNAL ;
    ANTENNADIFFAREA 0.445500 ;
    PORT
      LAYER met3 ;
        RECT 1496.000 1177.800 1500.000 1178.400 ;
    END
  END wbs_dat_o[13]
  PIN wbs_dat_o[14]
    DIRECTION OUTPUT TRISTATE ;
    USE SIGNAL ;
    ANTENNADIFFAREA 0.445500 ;
    PORT
      LAYER met3 ;
        RECT 1496.000 1190.040 1500.000 1190.640 ;
    END
  END wbs_dat_o[14]
  PIN wbs_dat_o[15]
    DIRECTION OUTPUT TRISTATE ;
    USE SIGNAL ;
    ANTENNADIFFAREA 0.445500 ;
    PORT
      LAYER met3 ;
        RECT 1496.000 1202.280 1500.000 1202.880 ;
    END
  END wbs_dat_o[15]
  PIN wbs_dat_o[16]
    DIRECTION OUTPUT TRISTATE ;
    USE SIGNAL ;
    ANTENNADIFFAREA 0.445500 ;
    PORT
      LAYER met3 ;
        RECT 1496.000 1214.520 1500.000 1215.120 ;
    END
  END wbs_dat_o[16]
  PIN wbs_dat_o[17]
    DIRECTION OUTPUT TRISTATE ;
    USE SIGNAL ;
    ANTENNADIFFAREA 0.795200 ;
    PORT
      LAYER met3 ;
        RECT 1496.000 1226.760 1500.000 1227.360 ;
    END
  END wbs_dat_o[17]
  PIN wbs_dat_o[18]
    DIRECTION OUTPUT TRISTATE ;
    USE SIGNAL ;
    ANTENNADIFFAREA 0.445500 ;
    PORT
      LAYER met3 ;
        RECT 1496.000 1239.000 1500.000 1239.600 ;
    END
  END wbs_dat_o[18]
  PIN wbs_dat_o[19]
    DIRECTION OUTPUT TRISTATE ;
    USE SIGNAL ;
    ANTENNADIFFAREA 0.445500 ;
    PORT
      LAYER met3 ;
        RECT 1496.000 1251.240 1500.000 1251.840 ;
    END
  END wbs_dat_o[19]
  PIN wbs_dat_o[1]
    DIRECTION OUTPUT TRISTATE ;
    USE SIGNAL ;
    ANTENNADIFFAREA 0.445500 ;
    PORT
      LAYER met3 ;
        RECT 1496.000 1030.920 1500.000 1031.520 ;
    END
  END wbs_dat_o[1]
  PIN wbs_dat_o[20]
    DIRECTION OUTPUT TRISTATE ;
    USE SIGNAL ;
    ANTENNADIFFAREA 0.445500 ;
    PORT
      LAYER met3 ;
        RECT 1496.000 1263.480 1500.000 1264.080 ;
    END
  END wbs_dat_o[20]
  PIN wbs_dat_o[21]
    DIRECTION OUTPUT TRISTATE ;
    USE SIGNAL ;
    ANTENNADIFFAREA 0.795200 ;
    PORT
      LAYER met3 ;
        RECT 1496.000 1275.720 1500.000 1276.320 ;
    END
  END wbs_dat_o[21]
  PIN wbs_dat_o[22]
    DIRECTION OUTPUT TRISTATE ;
    USE SIGNAL ;
    ANTENNADIFFAREA 0.795200 ;
    PORT
      LAYER met3 ;
        RECT 1496.000 1287.960 1500.000 1288.560 ;
    END
  END wbs_dat_o[22]
  PIN wbs_dat_o[23]
    DIRECTION OUTPUT TRISTATE ;
    USE SIGNAL ;
    ANTENNADIFFAREA 0.445500 ;
    PORT
      LAYER met3 ;
        RECT 1496.000 1300.200 1500.000 1300.800 ;
    END
  END wbs_dat_o[23]
  PIN wbs_dat_o[24]
    DIRECTION OUTPUT TRISTATE ;
    USE SIGNAL ;
    ANTENNADIFFAREA 0.445500 ;
    PORT
      LAYER met3 ;
        RECT 1496.000 1312.440 1500.000 1313.040 ;
    END
  END wbs_dat_o[24]
  PIN wbs_dat_o[25]
    DIRECTION OUTPUT TRISTATE ;
    USE SIGNAL ;
    ANTENNADIFFAREA 0.445500 ;
    PORT
      LAYER met3 ;
        RECT 1496.000 1324.680 1500.000 1325.280 ;
    END
  END wbs_dat_o[25]
  PIN wbs_dat_o[26]
    DIRECTION OUTPUT TRISTATE ;
    USE SIGNAL ;
    ANTENNADIFFAREA 0.795200 ;
    PORT
      LAYER met3 ;
        RECT 1496.000 1336.920 1500.000 1337.520 ;
    END
  END wbs_dat_o[26]
  PIN wbs_dat_o[27]
    DIRECTION OUTPUT TRISTATE ;
    USE SIGNAL ;
    ANTENNADIFFAREA 0.445500 ;
    PORT
      LAYER met3 ;
        RECT 1496.000 1349.160 1500.000 1349.760 ;
    END
  END wbs_dat_o[27]
  PIN wbs_dat_o[28]
    DIRECTION OUTPUT TRISTATE ;
    USE SIGNAL ;
    ANTENNADIFFAREA 0.445500 ;
    PORT
      LAYER met3 ;
        RECT 1496.000 1361.400 1500.000 1362.000 ;
    END
  END wbs_dat_o[28]
  PIN wbs_dat_o[29]
    DIRECTION OUTPUT TRISTATE ;
    USE SIGNAL ;
    ANTENNADIFFAREA 0.445500 ;
    PORT
      LAYER met3 ;
        RECT 1496.000 1373.640 1500.000 1374.240 ;
    END
  END wbs_dat_o[29]
  PIN wbs_dat_o[2]
    DIRECTION OUTPUT TRISTATE ;
    USE SIGNAL ;
    ANTENNADIFFAREA 0.445500 ;
    PORT
      LAYER met3 ;
        RECT 1496.000 1043.160 1500.000 1043.760 ;
    END
  END wbs_dat_o[2]
  PIN wbs_dat_o[30]
    DIRECTION OUTPUT TRISTATE ;
    USE SIGNAL ;
    ANTENNADIFFAREA 0.795200 ;
    PORT
      LAYER met3 ;
        RECT 1496.000 1385.880 1500.000 1386.480 ;
    END
  END wbs_dat_o[30]
  PIN wbs_dat_o[31]
    DIRECTION OUTPUT TRISTATE ;
    USE SIGNAL ;
    ANTENNADIFFAREA 0.445500 ;
    PORT
      LAYER met3 ;
        RECT 1496.000 1398.120 1500.000 1398.720 ;
    END
  END wbs_dat_o[31]
  PIN wbs_dat_o[3]
    DIRECTION OUTPUT TRISTATE ;
    USE SIGNAL ;
    ANTENNADIFFAREA 0.445500 ;
    PORT
      LAYER met3 ;
        RECT 1496.000 1055.400 1500.000 1056.000 ;
    END
  END wbs_dat_o[3]
  PIN wbs_dat_o[4]
    DIRECTION OUTPUT TRISTATE ;
    USE SIGNAL ;
    ANTENNADIFFAREA 0.795200 ;
    PORT
      LAYER met3 ;
        RECT 1496.000 1067.640 1500.000 1068.240 ;
    END
  END wbs_dat_o[4]
  PIN wbs_dat_o[5]
    DIRECTION OUTPUT TRISTATE ;
    USE SIGNAL ;
    ANTENNADIFFAREA 0.445500 ;
    PORT
      LAYER met3 ;
        RECT 1496.000 1079.880 1500.000 1080.480 ;
    END
  END wbs_dat_o[5]
  PIN wbs_dat_o[6]
    DIRECTION OUTPUT TRISTATE ;
    USE SIGNAL ;
    ANTENNADIFFAREA 0.445500 ;
    PORT
      LAYER met3 ;
        RECT 1496.000 1092.120 1500.000 1092.720 ;
    END
  END wbs_dat_o[6]
  PIN wbs_dat_o[7]
    DIRECTION OUTPUT TRISTATE ;
    USE SIGNAL ;
    ANTENNADIFFAREA 0.445500 ;
    PORT
      LAYER met3 ;
        RECT 1496.000 1104.360 1500.000 1104.960 ;
    END
  END wbs_dat_o[7]
  PIN wbs_dat_o[8]
    DIRECTION OUTPUT TRISTATE ;
    USE SIGNAL ;
    ANTENNADIFFAREA 0.795200 ;
    PORT
      LAYER met3 ;
        RECT 1496.000 1116.600 1500.000 1117.200 ;
    END
  END wbs_dat_o[8]
  PIN wbs_dat_o[9]
    DIRECTION OUTPUT TRISTATE ;
    USE SIGNAL ;
    ANTENNADIFFAREA 0.445500 ;
    PORT
      LAYER met3 ;
        RECT 1496.000 1128.840 1500.000 1129.440 ;
    END
  END wbs_dat_o[9]
  PIN wbs_sel_i[0]
    DIRECTION INPUT ;
    USE SIGNAL ;
    ANTENNAGATEAREA 0.990000 ;
    PORT
      LAYER met3 ;
        RECT 1496.000 1410.360 1500.000 1410.960 ;
    END
  END wbs_sel_i[0]
  PIN wbs_sel_i[1]
    DIRECTION INPUT ;
    USE SIGNAL ;
    ANTENNAGATEAREA 0.990000 ;
    PORT
      LAYER met3 ;
        RECT 1496.000 1422.600 1500.000 1423.200 ;
    END
  END wbs_sel_i[1]
  PIN wbs_sel_i[2]
    DIRECTION INPUT ;
    USE SIGNAL ;
    ANTENNAGATEAREA 0.990000 ;
    PORT
      LAYER met3 ;
        RECT 1496.000 1434.840 1500.000 1435.440 ;
    END
  END wbs_sel_i[2]
  PIN wbs_sel_i[3]
    DIRECTION INPUT ;
    USE SIGNAL ;
    ANTENNAGATEAREA 0.990000 ;
    PORT
      LAYER met3 ;
        RECT 1496.000 1447.080 1500.000 1447.680 ;
    END
  END wbs_sel_i[3]
  PIN wbs_stb_i
    DIRECTION INPUT ;
    USE SIGNAL ;
    ANTENNAGATEAREA 0.742500 ;
    PORT
      LAYER met2 ;
        RECT 68.630 0.000 68.910 4.000 ;
    END
  END wbs_stb_i
  PIN wbs_we_i
    DIRECTION INPUT ;
    USE SIGNAL ;
    ANTENNAGATEAREA 0.159000 ;
    PORT
      LAYER met2 ;
        RECT 90.250 0.000 90.530 4.000 ;
    END
  END wbs_we_i
  OBS
      LAYER li1 ;
        RECT 5.520 10.795 1494.080 1487.925 ;
      LAYER met1 ;
        RECT 4.670 10.640 1494.470 1488.080 ;
      LAYER met2 ;
        RECT 4.690 1495.720 25.110 1496.000 ;
        RECT 25.950 1495.720 48.110 1496.000 ;
        RECT 48.950 1495.720 71.110 1496.000 ;
        RECT 71.950 1495.720 94.110 1496.000 ;
        RECT 94.950 1495.720 117.110 1496.000 ;
        RECT 117.950 1495.720 140.110 1496.000 ;
        RECT 140.950 1495.720 163.110 1496.000 ;
        RECT 163.950 1495.720 186.110 1496.000 ;
        RECT 186.950 1495.720 209.110 1496.000 ;
        RECT 209.950 1495.720 232.110 1496.000 ;
        RECT 232.950 1495.720 255.110 1496.000 ;
        RECT 255.950 1495.720 278.110 1496.000 ;
        RECT 278.950 1495.720 301.110 1496.000 ;
        RECT 301.950 1495.720 324.110 1496.000 ;
        RECT 324.950 1495.720 347.110 1496.000 ;
        RECT 347.950 1495.720 370.110 1496.000 ;
        RECT 370.950 1495.720 393.110 1496.000 ;
        RECT 393.950 1495.720 416.110 1496.000 ;
        RECT 416.950 1495.720 439.110 1496.000 ;
        RECT 439.950 1495.720 462.110 1496.000 ;
        RECT 462.950 1495.720 485.110 1496.000 ;
        RECT 485.950 1495.720 508.110 1496.000 ;
        RECT 508.950 1495.720 531.110 1496.000 ;
        RECT 531.950 1495.720 554.110 1496.000 ;
        RECT 554.950 1495.720 577.110 1496.000 ;
        RECT 577.950 1495.720 600.110 1496.000 ;
        RECT 600.950 1495.720 623.110 1496.000 ;
        RECT 623.950 1495.720 646.110 1496.000 ;
        RECT 646.950 1495.720 669.110 1496.000 ;
        RECT 669.950 1495.720 692.110 1496.000 ;
        RECT 692.950 1495.720 715.110 1496.000 ;
        RECT 715.950 1495.720 738.110 1496.000 ;
        RECT 738.950 1495.720 761.110 1496.000 ;
        RECT 761.950 1495.720 784.110 1496.000 ;
        RECT 784.950 1495.720 807.110 1496.000 ;
        RECT 807.950 1495.720 830.110 1496.000 ;
        RECT 830.950 1495.720 853.110 1496.000 ;
        RECT 853.950 1495.720 876.110 1496.000 ;
        RECT 876.950 1495.720 899.110 1496.000 ;
        RECT 899.950 1495.720 922.110 1496.000 ;
        RECT 922.950 1495.720 945.110 1496.000 ;
        RECT 945.950 1495.720 968.110 1496.000 ;
        RECT 968.950 1495.720 991.110 1496.000 ;
        RECT 991.950 1495.720 1014.110 1496.000 ;
        RECT 1014.950 1495.720 1037.110 1496.000 ;
        RECT 1037.950 1495.720 1060.110 1496.000 ;
        RECT 1060.950 1495.720 1083.110 1496.000 ;
        RECT 1083.950 1495.720 1106.110 1496.000 ;
        RECT 1106.950 1495.720 1129.110 1496.000 ;
        RECT 1129.950 1495.720 1152.110 1496.000 ;
        RECT 1152.950 1495.720 1175.110 1496.000 ;
        RECT 1175.950 1495.720 1198.110 1496.000 ;
        RECT 1198.950 1495.720 1221.110 1496.000 ;
        RECT 1221.950 1495.720 1244.110 1496.000 ;
        RECT 1244.950 1495.720 1267.110 1496.000 ;
        RECT 1267.950 1495.720 1290.110 1496.000 ;
        RECT 1290.950 1495.720 1313.110 1496.000 ;
        RECT 1313.950 1495.720 1336.110 1496.000 ;
        RECT 1336.950 1495.720 1359.110 1496.000 ;
        RECT 1359.950 1495.720 1382.110 1496.000 ;
        RECT 1382.950 1495.720 1405.110 1496.000 ;
        RECT 1405.950 1495.720 1428.110 1496.000 ;
        RECT 1428.950 1495.720 1451.110 1496.000 ;
        RECT 1451.950 1495.720 1474.110 1496.000 ;
        RECT 1474.950 1495.720 1494.450 1496.000 ;
        RECT 4.690 4.280 1494.450 1495.720 ;
        RECT 4.690 3.670 25.110 4.280 ;
        RECT 25.950 3.670 46.730 4.280 ;
        RECT 47.570 3.670 68.350 4.280 ;
        RECT 69.190 3.670 89.970 4.280 ;
        RECT 90.810 3.670 111.590 4.280 ;
        RECT 112.430 3.670 133.210 4.280 ;
        RECT 134.050 3.670 154.830 4.280 ;
        RECT 155.670 3.670 176.450 4.280 ;
        RECT 177.290 3.670 198.070 4.280 ;
        RECT 198.910 3.670 219.690 4.280 ;
        RECT 220.530 3.670 241.310 4.280 ;
        RECT 242.150 3.670 262.930 4.280 ;
        RECT 263.770 3.670 284.550 4.280 ;
        RECT 285.390 3.670 306.170 4.280 ;
        RECT 307.010 3.670 327.790 4.280 ;
        RECT 328.630 3.670 349.410 4.280 ;
        RECT 350.250 3.670 371.030 4.280 ;
        RECT 371.870 3.670 392.650 4.280 ;
        RECT 393.490 3.670 414.270 4.280 ;
        RECT 415.110 3.670 435.890 4.280 ;
        RECT 436.730 3.670 457.510 4.280 ;
        RECT 458.350 3.670 479.130 4.280 ;
        RECT 479.970 3.670 500.750 4.280 ;
        RECT 501.590 3.670 522.370 4.280 ;
        RECT 523.210 3.670 543.990 4.280 ;
        RECT 544.830 3.670 565.610 4.280 ;
        RECT 566.450 3.670 587.230 4.280 ;
        RECT 588.070 3.670 608.850 4.280 ;
        RECT 609.690 3.670 630.470 4.280 ;
        RECT 631.310 3.670 652.090 4.280 ;
        RECT 652.930 3.670 673.710 4.280 ;
        RECT 674.550 3.670 695.330 4.280 ;
        RECT 696.170 3.670 716.950 4.280 ;
        RECT 717.790 3.670 738.570 4.280 ;
        RECT 739.410 3.670 760.190 4.280 ;
        RECT 761.030 3.670 781.810 4.280 ;
        RECT 782.650 3.670 803.430 4.280 ;
        RECT 804.270 3.670 825.050 4.280 ;
        RECT 825.890 3.670 846.670 4.280 ;
        RECT 847.510 3.670 868.290 4.280 ;
        RECT 869.130 3.670 889.910 4.280 ;
        RECT 890.750 3.670 911.530 4.280 ;
        RECT 912.370 3.670 933.150 4.280 ;
        RECT 933.990 3.670 954.770 4.280 ;
        RECT 955.610 3.670 976.390 4.280 ;
        RECT 977.230 3.670 998.010 4.280 ;
        RECT 998.850 3.670 1019.630 4.280 ;
        RECT 1020.470 3.670 1041.250 4.280 ;
        RECT 1042.090 3.670 1062.870 4.280 ;
        RECT 1063.710 3.670 1084.490 4.280 ;
        RECT 1085.330 3.670 1106.110 4.280 ;
        RECT 1106.950 3.670 1127.730 4.280 ;
        RECT 1128.570 3.670 1149.350 4.280 ;
        RECT 1150.190 3.670 1170.970 4.280 ;
        RECT 1171.810 3.670 1192.590 4.280 ;
        RECT 1193.430 3.670 1214.210 4.280 ;
        RECT 1215.050 3.670 1235.830 4.280 ;
        RECT 1236.670 3.670 1257.450 4.280 ;
        RECT 1258.290 3.670 1279.070 4.280 ;
        RECT 1279.910 3.670 1300.690 4.280 ;
        RECT 1301.530 3.670 1322.310 4.280 ;
        RECT 1323.150 3.670 1343.930 4.280 ;
        RECT 1344.770 3.670 1365.550 4.280 ;
        RECT 1366.390 3.670 1387.170 4.280 ;
        RECT 1388.010 3.670 1408.790 4.280 ;
        RECT 1409.630 3.670 1430.410 4.280 ;
        RECT 1431.250 3.670 1452.030 4.280 ;
        RECT 1452.870 3.670 1473.650 4.280 ;
        RECT 1474.490 3.670 1494.450 4.280 ;
      LAYER met3 ;
        RECT 3.990 1464.400 1496.000 1488.005 ;
        RECT 4.400 1463.000 1496.000 1464.400 ;
        RECT 3.990 1448.080 1496.000 1463.000 ;
        RECT 3.990 1446.680 1495.600 1448.080 ;
        RECT 3.990 1445.360 1496.000 1446.680 ;
        RECT 4.400 1443.960 1496.000 1445.360 ;
        RECT 3.990 1435.840 1496.000 1443.960 ;
        RECT 3.990 1434.440 1495.600 1435.840 ;
        RECT 3.990 1426.320 1496.000 1434.440 ;
        RECT 4.400 1424.920 1496.000 1426.320 ;
        RECT 3.990 1423.600 1496.000 1424.920 ;
        RECT 3.990 1422.200 1495.600 1423.600 ;
        RECT 3.990 1411.360 1496.000 1422.200 ;
        RECT 3.990 1409.960 1495.600 1411.360 ;
        RECT 3.990 1407.280 1496.000 1409.960 ;
        RECT 4.400 1405.880 1496.000 1407.280 ;
        RECT 3.990 1399.120 1496.000 1405.880 ;
        RECT 3.990 1397.720 1495.600 1399.120 ;
        RECT 3.990 1388.240 1496.000 1397.720 ;
        RECT 4.400 1386.880 1496.000 1388.240 ;
        RECT 4.400 1386.840 1495.600 1386.880 ;
        RECT 3.990 1385.480 1495.600 1386.840 ;
        RECT 3.990 1374.640 1496.000 1385.480 ;
        RECT 3.990 1373.240 1495.600 1374.640 ;
        RECT 3.990 1369.200 1496.000 1373.240 ;
        RECT 4.400 1367.800 1496.000 1369.200 ;
        RECT 3.990 1362.400 1496.000 1367.800 ;
        RECT 3.990 1361.000 1495.600 1362.400 ;
        RECT 3.990 1350.160 1496.000 1361.000 ;
        RECT 4.400 1348.760 1495.600 1350.160 ;
        RECT 3.990 1337.920 1496.000 1348.760 ;
        RECT 3.990 1336.520 1495.600 1337.920 ;
        RECT 3.990 1331.120 1496.000 1336.520 ;
        RECT 4.400 1329.720 1496.000 1331.120 ;
        RECT 3.990 1325.680 1496.000 1329.720 ;
        RECT 3.990 1324.280 1495.600 1325.680 ;
        RECT 3.990 1313.440 1496.000 1324.280 ;
        RECT 3.990 1312.080 1495.600 1313.440 ;
        RECT 4.400 1312.040 1495.600 1312.080 ;
        RECT 4.400 1310.680 1496.000 1312.040 ;
        RECT 3.990 1301.200 1496.000 1310.680 ;
        RECT 3.990 1299.800 1495.600 1301.200 ;
        RECT 3.990 1293.040 1496.000 1299.800 ;
        RECT 4.400 1291.640 1496.000 1293.040 ;
        RECT 3.990 1288.960 1496.000 1291.640 ;
        RECT 3.990 1287.560 1495.600 1288.960 ;
        RECT 3.990 1276.720 1496.000 1287.560 ;
        RECT 3.990 1275.320 1495.600 1276.720 ;
        RECT 3.990 1274.000 1496.000 1275.320 ;
        RECT 4.400 1272.600 1496.000 1274.000 ;
        RECT 3.990 1264.480 1496.000 1272.600 ;
        RECT 3.990 1263.080 1495.600 1264.480 ;
        RECT 3.990 1254.960 1496.000 1263.080 ;
        RECT 4.400 1253.560 1496.000 1254.960 ;
        RECT 3.990 1252.240 1496.000 1253.560 ;
        RECT 3.990 1250.840 1495.600 1252.240 ;
        RECT 3.990 1240.000 1496.000 1250.840 ;
        RECT 3.990 1238.600 1495.600 1240.000 ;
        RECT 3.990 1235.920 1496.000 1238.600 ;
        RECT 4.400 1234.520 1496.000 1235.920 ;
        RECT 3.990 1227.760 1496.000 1234.520 ;
        RECT 3.990 1226.360 1495.600 1227.760 ;
        RECT 3.990 1216.880 1496.000 1226.360 ;
        RECT 4.400 1215.520 1496.000 1216.880 ;
        RECT 4.400 1215.480 1495.600 1215.520 ;
        RECT 3.990 1214.120 1495.600 1215.480 ;
        RECT 3.990 1203.280 1496.000 1214.120 ;
        RECT 3.990 1201.880 1495.600 1203.280 ;
        RECT 3.990 1197.840 1496.000 1201.880 ;
        RECT 4.400 1196.440 1496.000 1197.840 ;
        RECT 3.990 1191.040 1496.000 1196.440 ;
        RECT 3.990 1189.640 1495.600 1191.040 ;
        RECT 3.990 1178.800 1496.000 1189.640 ;
        RECT 4.400 1177.400 1495.600 1178.800 ;
        RECT 3.990 1166.560 1496.000 1177.400 ;
        RECT 3.990 1165.160 1495.600 1166.560 ;
        RECT 3.990 1159.760 1496.000 1165.160 ;
        RECT 4.400 1158.360 1496.000 1159.760 ;
        RECT 3.990 1154.320 1496.000 1158.360 ;
        RECT 3.990 1152.920 1495.600 1154.320 ;
        RECT 3.990 1142.080 1496.000 1152.920 ;
        RECT 3.990 1140.720 1495.600 1142.080 ;
        RECT 4.400 1140.680 1495.600 1140.720 ;
        RECT 4.400 1139.320 1496.000 1140.680 ;
        RECT 3.990 1129.840 1496.000 1139.320 ;
        RECT 3.990 1128.440 1495.600 1129.840 ;
        RECT 3.990 1121.680 1496.000 1128.440 ;
        RECT 4.400 1120.280 1496.000 1121.680 ;
        RECT 3.990 1117.600 1496.000 1120.280 ;
        RECT 3.990 1116.200 1495.600 1117.600 ;
        RECT 3.990 1105.360 1496.000 1116.200 ;
        RECT 3.990 1103.960 1495.600 1105.360 ;
        RECT 3.990 1102.640 1496.000 1103.960 ;
        RECT 4.400 1101.240 1496.000 1102.640 ;
        RECT 3.990 1093.120 1496.000 1101.240 ;
        RECT 3.990 1091.720 1495.600 1093.120 ;
        RECT 3.990 1083.600 1496.000 1091.720 ;
        RECT 4.400 1082.200 1496.000 1083.600 ;
        RECT 3.990 1080.880 1496.000 1082.200 ;
        RECT 3.990 1079.480 1495.600 1080.880 ;
        RECT 3.990 1068.640 1496.000 1079.480 ;
        RECT 3.990 1067.240 1495.600 1068.640 ;
        RECT 3.990 1064.560 1496.000 1067.240 ;
        RECT 4.400 1063.160 1496.000 1064.560 ;
        RECT 3.990 1056.400 1496.000 1063.160 ;
        RECT 3.990 1055.000 1495.600 1056.400 ;
        RECT 3.990 1045.520 1496.000 1055.000 ;
        RECT 4.400 1044.160 1496.000 1045.520 ;
        RECT 4.400 1044.120 1495.600 1044.160 ;
        RECT 3.990 1042.760 1495.600 1044.120 ;
        RECT 3.990 1031.920 1496.000 1042.760 ;
        RECT 3.990 1030.520 1495.600 1031.920 ;
        RECT 3.990 1026.480 1496.000 1030.520 ;
        RECT 4.400 1025.080 1496.000 1026.480 ;
        RECT 3.990 1019.680 1496.000 1025.080 ;
        RECT 3.990 1018.280 1495.600 1019.680 ;
        RECT 3.990 1007.440 1496.000 1018.280 ;
        RECT 4.400 1006.040 1495.600 1007.440 ;
        RECT 3.990 995.200 1496.000 1006.040 ;
        RECT 3.990 993.800 1495.600 995.200 ;
        RECT 3.990 988.400 1496.000 993.800 ;
        RECT 4.400 987.000 1496.000 988.400 ;
        RECT 3.990 982.960 1496.000 987.000 ;
        RECT 3.990 981.560 1495.600 982.960 ;
        RECT 3.990 970.720 1496.000 981.560 ;
        RECT 3.990 969.360 1495.600 970.720 ;
        RECT 4.400 969.320 1495.600 969.360 ;
        RECT 4.400 967.960 1496.000 969.320 ;
        RECT 3.990 958.480 1496.000 967.960 ;
        RECT 3.990 957.080 1495.600 958.480 ;
        RECT 3.990 950.320 1496.000 957.080 ;
        RECT 4.400 948.920 1496.000 950.320 ;
        RECT 3.990 946.240 1496.000 948.920 ;
        RECT 3.990 944.840 1495.600 946.240 ;
        RECT 3.990 934.000 1496.000 944.840 ;
        RECT 3.990 932.600 1495.600 934.000 ;
        RECT 3.990 931.280 1496.000 932.600 ;
        RECT 4.400 929.880 1496.000 931.280 ;
        RECT 3.990 921.760 1496.000 929.880 ;
        RECT 3.990 920.360 1495.600 921.760 ;
        RECT 3.990 912.240 1496.000 920.360 ;
        RECT 4.400 910.840 1496.000 912.240 ;
        RECT 3.990 909.520 1496.000 910.840 ;
        RECT 3.990 908.120 1495.600 909.520 ;
        RECT 3.990 897.280 1496.000 908.120 ;
        RECT 3.990 895.880 1495.600 897.280 ;
        RECT 3.990 893.200 1496.000 895.880 ;
        RECT 4.400 891.800 1496.000 893.200 ;
        RECT 3.990 885.040 1496.000 891.800 ;
        RECT 3.990 883.640 1495.600 885.040 ;
        RECT 3.990 874.160 1496.000 883.640 ;
        RECT 4.400 872.800 1496.000 874.160 ;
        RECT 4.400 872.760 1495.600 872.800 ;
        RECT 3.990 871.400 1495.600 872.760 ;
        RECT 3.990 860.560 1496.000 871.400 ;
        RECT 3.990 859.160 1495.600 860.560 ;
        RECT 3.990 855.120 1496.000 859.160 ;
        RECT 4.400 853.720 1496.000 855.120 ;
        RECT 3.990 848.320 1496.000 853.720 ;
        RECT 3.990 846.920 1495.600 848.320 ;
        RECT 3.990 836.080 1496.000 846.920 ;
        RECT 4.400 834.680 1495.600 836.080 ;
        RECT 3.990 823.840 1496.000 834.680 ;
        RECT 3.990 822.440 1495.600 823.840 ;
        RECT 3.990 817.040 1496.000 822.440 ;
        RECT 4.400 815.640 1496.000 817.040 ;
        RECT 3.990 811.600 1496.000 815.640 ;
        RECT 3.990 810.200 1495.600 811.600 ;
        RECT 3.990 799.360 1496.000 810.200 ;
        RECT 3.990 798.000 1495.600 799.360 ;
        RECT 4.400 797.960 1495.600 798.000 ;
        RECT 4.400 796.600 1496.000 797.960 ;
        RECT 3.990 787.120 1496.000 796.600 ;
        RECT 3.990 785.720 1495.600 787.120 ;
        RECT 3.990 778.960 1496.000 785.720 ;
        RECT 4.400 777.560 1496.000 778.960 ;
        RECT 3.990 774.880 1496.000 777.560 ;
        RECT 3.990 773.480 1495.600 774.880 ;
        RECT 3.990 762.640 1496.000 773.480 ;
        RECT 3.990 761.240 1495.600 762.640 ;
        RECT 3.990 759.920 1496.000 761.240 ;
        RECT 4.400 758.520 1496.000 759.920 ;
        RECT 3.990 750.400 1496.000 758.520 ;
        RECT 3.990 749.000 1495.600 750.400 ;
        RECT 3.990 740.880 1496.000 749.000 ;
        RECT 4.400 739.480 1496.000 740.880 ;
        RECT 3.990 738.160 1496.000 739.480 ;
        RECT 3.990 736.760 1495.600 738.160 ;
        RECT 3.990 725.920 1496.000 736.760 ;
        RECT 3.990 724.520 1495.600 725.920 ;
        RECT 3.990 721.840 1496.000 724.520 ;
        RECT 4.400 720.440 1496.000 721.840 ;
        RECT 3.990 713.680 1496.000 720.440 ;
        RECT 3.990 712.280 1495.600 713.680 ;
        RECT 3.990 702.800 1496.000 712.280 ;
        RECT 4.400 701.440 1496.000 702.800 ;
        RECT 4.400 701.400 1495.600 701.440 ;
        RECT 3.990 700.040 1495.600 701.400 ;
        RECT 3.990 689.200 1496.000 700.040 ;
        RECT 3.990 687.800 1495.600 689.200 ;
        RECT 3.990 683.760 1496.000 687.800 ;
        RECT 4.400 682.360 1496.000 683.760 ;
        RECT 3.990 676.960 1496.000 682.360 ;
        RECT 3.990 675.560 1495.600 676.960 ;
        RECT 3.990 664.720 1496.000 675.560 ;
        RECT 4.400 663.320 1495.600 664.720 ;
        RECT 3.990 652.480 1496.000 663.320 ;
        RECT 3.990 651.080 1495.600 652.480 ;
        RECT 3.990 645.680 1496.000 651.080 ;
        RECT 4.400 644.280 1496.000 645.680 ;
        RECT 3.990 640.240 1496.000 644.280 ;
        RECT 3.990 638.840 1495.600 640.240 ;
        RECT 3.990 628.000 1496.000 638.840 ;
        RECT 3.990 626.640 1495.600 628.000 ;
        RECT 4.400 626.600 1495.600 626.640 ;
        RECT 4.400 625.240 1496.000 626.600 ;
        RECT 3.990 615.760 1496.000 625.240 ;
        RECT 3.990 614.360 1495.600 615.760 ;
        RECT 3.990 607.600 1496.000 614.360 ;
        RECT 4.400 606.200 1496.000 607.600 ;
        RECT 3.990 603.520 1496.000 606.200 ;
        RECT 3.990 602.120 1495.600 603.520 ;
        RECT 3.990 591.280 1496.000 602.120 ;
        RECT 3.990 589.880 1495.600 591.280 ;
        RECT 3.990 588.560 1496.000 589.880 ;
        RECT 4.400 587.160 1496.000 588.560 ;
        RECT 3.990 579.040 1496.000 587.160 ;
        RECT 3.990 577.640 1495.600 579.040 ;
        RECT 3.990 569.520 1496.000 577.640 ;
        RECT 4.400 568.120 1496.000 569.520 ;
        RECT 3.990 566.800 1496.000 568.120 ;
        RECT 3.990 565.400 1495.600 566.800 ;
        RECT 3.990 554.560 1496.000 565.400 ;
        RECT 3.990 553.160 1495.600 554.560 ;
        RECT 3.990 550.480 1496.000 553.160 ;
        RECT 4.400 549.080 1496.000 550.480 ;
        RECT 3.990 542.320 1496.000 549.080 ;
        RECT 3.990 540.920 1495.600 542.320 ;
        RECT 3.990 531.440 1496.000 540.920 ;
        RECT 4.400 530.080 1496.000 531.440 ;
        RECT 4.400 530.040 1495.600 530.080 ;
        RECT 3.990 528.680 1495.600 530.040 ;
        RECT 3.990 517.840 1496.000 528.680 ;
        RECT 3.990 516.440 1495.600 517.840 ;
        RECT 3.990 512.400 1496.000 516.440 ;
        RECT 4.400 511.000 1496.000 512.400 ;
        RECT 3.990 505.600 1496.000 511.000 ;
        RECT 3.990 504.200 1495.600 505.600 ;
        RECT 3.990 493.360 1496.000 504.200 ;
        RECT 4.400 491.960 1495.600 493.360 ;
        RECT 3.990 481.120 1496.000 491.960 ;
        RECT 3.990 479.720 1495.600 481.120 ;
        RECT 3.990 474.320 1496.000 479.720 ;
        RECT 4.400 472.920 1496.000 474.320 ;
        RECT 3.990 468.880 1496.000 472.920 ;
        RECT 3.990 467.480 1495.600 468.880 ;
        RECT 3.990 456.640 1496.000 467.480 ;
        RECT 3.990 455.280 1495.600 456.640 ;
        RECT 4.400 455.240 1495.600 455.280 ;
        RECT 4.400 453.880 1496.000 455.240 ;
        RECT 3.990 444.400 1496.000 453.880 ;
        RECT 3.990 443.000 1495.600 444.400 ;
        RECT 3.990 436.240 1496.000 443.000 ;
        RECT 4.400 434.840 1496.000 436.240 ;
        RECT 3.990 432.160 1496.000 434.840 ;
        RECT 3.990 430.760 1495.600 432.160 ;
        RECT 3.990 419.920 1496.000 430.760 ;
        RECT 3.990 418.520 1495.600 419.920 ;
        RECT 3.990 417.200 1496.000 418.520 ;
        RECT 4.400 415.800 1496.000 417.200 ;
        RECT 3.990 407.680 1496.000 415.800 ;
        RECT 3.990 406.280 1495.600 407.680 ;
        RECT 3.990 398.160 1496.000 406.280 ;
        RECT 4.400 396.760 1496.000 398.160 ;
        RECT 3.990 395.440 1496.000 396.760 ;
        RECT 3.990 394.040 1495.600 395.440 ;
        RECT 3.990 383.200 1496.000 394.040 ;
        RECT 3.990 381.800 1495.600 383.200 ;
        RECT 3.990 379.120 1496.000 381.800 ;
        RECT 4.400 377.720 1496.000 379.120 ;
        RECT 3.990 370.960 1496.000 377.720 ;
        RECT 3.990 369.560 1495.600 370.960 ;
        RECT 3.990 360.080 1496.000 369.560 ;
        RECT 4.400 358.720 1496.000 360.080 ;
        RECT 4.400 358.680 1495.600 358.720 ;
        RECT 3.990 357.320 1495.600 358.680 ;
        RECT 3.990 346.480 1496.000 357.320 ;
        RECT 3.990 345.080 1495.600 346.480 ;
        RECT 3.990 341.040 1496.000 345.080 ;
        RECT 4.400 339.640 1496.000 341.040 ;
        RECT 3.990 334.240 1496.000 339.640 ;
        RECT 3.990 332.840 1495.600 334.240 ;
        RECT 3.990 322.000 1496.000 332.840 ;
        RECT 4.400 320.600 1495.600 322.000 ;
        RECT 3.990 309.760 1496.000 320.600 ;
        RECT 3.990 308.360 1495.600 309.760 ;
        RECT 3.990 302.960 1496.000 308.360 ;
        RECT 4.400 301.560 1496.000 302.960 ;
        RECT 3.990 297.520 1496.000 301.560 ;
        RECT 3.990 296.120 1495.600 297.520 ;
        RECT 3.990 285.280 1496.000 296.120 ;
        RECT 3.990 283.920 1495.600 285.280 ;
        RECT 4.400 283.880 1495.600 283.920 ;
        RECT 4.400 282.520 1496.000 283.880 ;
        RECT 3.990 273.040 1496.000 282.520 ;
        RECT 3.990 271.640 1495.600 273.040 ;
        RECT 3.990 264.880 1496.000 271.640 ;
        RECT 4.400 263.480 1496.000 264.880 ;
        RECT 3.990 260.800 1496.000 263.480 ;
        RECT 3.990 259.400 1495.600 260.800 ;
        RECT 3.990 248.560 1496.000 259.400 ;
        RECT 3.990 247.160 1495.600 248.560 ;
        RECT 3.990 245.840 1496.000 247.160 ;
        RECT 4.400 244.440 1496.000 245.840 ;
        RECT 3.990 236.320 1496.000 244.440 ;
        RECT 3.990 234.920 1495.600 236.320 ;
        RECT 3.990 226.800 1496.000 234.920 ;
        RECT 4.400 225.400 1496.000 226.800 ;
        RECT 3.990 224.080 1496.000 225.400 ;
        RECT 3.990 222.680 1495.600 224.080 ;
        RECT 3.990 211.840 1496.000 222.680 ;
        RECT 3.990 210.440 1495.600 211.840 ;
        RECT 3.990 207.760 1496.000 210.440 ;
        RECT 4.400 206.360 1496.000 207.760 ;
        RECT 3.990 199.600 1496.000 206.360 ;
        RECT 3.990 198.200 1495.600 199.600 ;
        RECT 3.990 188.720 1496.000 198.200 ;
        RECT 4.400 187.360 1496.000 188.720 ;
        RECT 4.400 187.320 1495.600 187.360 ;
        RECT 3.990 185.960 1495.600 187.320 ;
        RECT 3.990 175.120 1496.000 185.960 ;
        RECT 3.990 173.720 1495.600 175.120 ;
        RECT 3.990 169.680 1496.000 173.720 ;
        RECT 4.400 168.280 1496.000 169.680 ;
        RECT 3.990 162.880 1496.000 168.280 ;
        RECT 3.990 161.480 1495.600 162.880 ;
        RECT 3.990 150.640 1496.000 161.480 ;
        RECT 4.400 149.240 1495.600 150.640 ;
        RECT 3.990 138.400 1496.000 149.240 ;
        RECT 3.990 137.000 1495.600 138.400 ;
        RECT 3.990 131.600 1496.000 137.000 ;
        RECT 4.400 130.200 1496.000 131.600 ;
        RECT 3.990 126.160 1496.000 130.200 ;
        RECT 3.990 124.760 1495.600 126.160 ;
        RECT 3.990 113.920 1496.000 124.760 ;
        RECT 3.990 112.560 1495.600 113.920 ;
        RECT 4.400 112.520 1495.600 112.560 ;
        RECT 4.400 111.160 1496.000 112.520 ;
        RECT 3.990 101.680 1496.000 111.160 ;
        RECT 3.990 100.280 1495.600 101.680 ;
        RECT 3.990 93.520 1496.000 100.280 ;
        RECT 4.400 92.120 1496.000 93.520 ;
        RECT 3.990 89.440 1496.000 92.120 ;
        RECT 3.990 88.040 1495.600 89.440 ;
        RECT 3.990 77.200 1496.000 88.040 ;
        RECT 3.990 75.800 1495.600 77.200 ;
        RECT 3.990 74.480 1496.000 75.800 ;
        RECT 4.400 73.080 1496.000 74.480 ;
        RECT 3.990 64.960 1496.000 73.080 ;
        RECT 3.990 63.560 1495.600 64.960 ;
        RECT 3.990 55.440 1496.000 63.560 ;
        RECT 4.400 54.040 1496.000 55.440 ;
        RECT 3.990 52.720 1496.000 54.040 ;
        RECT 3.990 51.320 1495.600 52.720 ;
        RECT 3.990 36.400 1496.000 51.320 ;
        RECT 4.400 35.000 1496.000 36.400 ;
        RECT 3.990 10.715 1496.000 35.000 ;
      LAYER met4 ;
        RECT 67.950 1126.120 174.240 1423.745 ;
        RECT 176.640 1126.120 177.540 1423.745 ;
        RECT 179.940 1126.120 180.840 1423.745 ;
        RECT 183.240 1126.120 184.140 1423.745 ;
        RECT 186.540 1126.120 187.440 1423.745 ;
        RECT 189.840 1126.120 190.740 1423.745 ;
        RECT 193.140 1126.120 194.040 1423.745 ;
        RECT 196.440 1126.120 197.340 1423.745 ;
        RECT 199.740 1126.120 327.840 1423.745 ;
        RECT 330.240 1126.120 331.140 1423.745 ;
        RECT 333.540 1126.120 334.440 1423.745 ;
        RECT 336.840 1126.120 337.740 1423.745 ;
        RECT 340.140 1126.740 341.040 1423.745 ;
        RECT 343.440 1126.740 344.340 1423.745 ;
        RECT 340.140 1126.120 344.340 1126.740 ;
        RECT 346.740 1126.120 347.640 1423.745 ;
        RECT 350.040 1126.120 350.940 1423.745 ;
        RECT 353.340 1126.120 481.440 1423.745 ;
        RECT 483.840 1126.120 484.740 1423.745 ;
        RECT 487.140 1126.120 488.040 1423.745 ;
        RECT 490.440 1126.740 491.340 1423.745 ;
        RECT 493.740 1126.740 494.640 1423.745 ;
        RECT 490.440 1126.120 494.640 1126.740 ;
        RECT 497.040 1126.120 497.940 1423.745 ;
        RECT 500.340 1126.120 501.240 1423.745 ;
        RECT 503.640 1126.740 504.540 1423.745 ;
        RECT 506.940 1126.740 635.040 1423.745 ;
        RECT 503.640 1126.120 635.040 1126.740 ;
        RECT 637.440 1126.120 638.340 1423.745 ;
        RECT 640.740 1126.120 641.640 1423.745 ;
        RECT 644.040 1126.120 644.940 1423.745 ;
        RECT 647.340 1126.120 648.240 1423.745 ;
        RECT 650.640 1126.120 651.540 1423.745 ;
        RECT 653.940 1126.120 654.840 1423.745 ;
        RECT 657.240 1126.120 658.140 1423.745 ;
        RECT 660.540 1126.120 788.640 1423.745 ;
        RECT 791.040 1126.120 791.940 1423.745 ;
        RECT 794.340 1126.120 795.240 1423.745 ;
        RECT 67.950 690.420 795.240 1126.120 ;
        RECT 67.950 526.120 174.240 690.420 ;
        RECT 176.640 526.120 177.540 690.420 ;
        RECT 179.940 689.800 481.440 690.420 ;
        RECT 179.940 526.120 327.840 689.800 ;
        RECT 330.240 526.120 331.140 689.800 ;
        RECT 333.540 526.120 481.440 689.800 ;
        RECT 483.840 526.120 484.740 690.420 ;
        RECT 487.140 526.120 635.040 690.420 ;
        RECT 637.440 526.120 638.340 690.420 ;
        RECT 640.740 526.120 788.640 690.420 ;
        RECT 791.040 526.120 791.940 690.420 ;
        RECT 794.340 526.120 795.240 690.420 ;
        RECT 67.950 90.420 795.240 526.120 ;
        RECT 67.950 13.095 174.240 90.420 ;
        RECT 176.640 13.095 177.540 90.420 ;
        RECT 179.940 89.800 481.440 90.420 ;
        RECT 179.940 13.095 327.840 89.800 ;
        RECT 330.240 13.095 331.140 89.800 ;
        RECT 333.540 13.095 481.440 89.800 ;
        RECT 483.840 13.095 484.740 90.420 ;
        RECT 487.140 13.095 635.040 90.420 ;
        RECT 637.440 13.095 638.340 90.420 ;
        RECT 640.740 13.095 788.640 90.420 ;
        RECT 791.040 13.095 791.940 90.420 ;
        RECT 794.340 13.095 795.240 90.420 ;
        RECT 797.640 13.095 798.540 1423.745 ;
        RECT 800.940 13.095 801.840 1423.745 ;
        RECT 804.240 13.095 805.140 1423.745 ;
        RECT 807.540 13.095 808.440 1423.745 ;
        RECT 810.840 13.095 811.740 1423.745 ;
        RECT 814.140 13.095 942.240 1423.745 ;
        RECT 944.640 13.095 945.540 1423.745 ;
        RECT 947.940 13.095 948.840 1423.745 ;
        RECT 951.240 13.095 952.140 1423.745 ;
        RECT 954.540 13.095 955.440 1423.745 ;
        RECT 957.840 13.095 958.740 1423.745 ;
        RECT 961.140 13.095 962.040 1423.745 ;
        RECT 964.440 13.095 965.340 1423.745 ;
        RECT 967.740 13.095 1095.840 1423.745 ;
        RECT 1098.240 13.095 1099.140 1423.745 ;
        RECT 1101.540 13.095 1102.440 1423.745 ;
        RECT 1104.840 13.095 1105.740 1423.745 ;
        RECT 1108.140 13.095 1109.040 1423.745 ;
        RECT 1111.440 13.095 1112.340 1423.745 ;
        RECT 1114.740 13.095 1115.640 1423.745 ;
        RECT 1118.040 13.095 1118.940 1423.745 ;
        RECT 1121.340 13.095 1249.440 1423.745 ;
        RECT 1251.840 13.095 1252.740 1423.745 ;
        RECT 1255.140 13.095 1256.040 1423.745 ;
        RECT 1258.440 13.095 1259.340 1423.745 ;
        RECT 1261.740 13.095 1262.640 1423.745 ;
        RECT 1265.040 13.095 1265.940 1423.745 ;
        RECT 1268.340 13.095 1269.240 1423.745 ;
        RECT 1271.640 13.095 1272.540 1423.745 ;
        RECT 1274.940 13.095 1403.040 1423.745 ;
        RECT 1405.440 13.095 1406.340 1423.745 ;
        RECT 1408.740 13.095 1409.640 1423.745 ;
        RECT 1412.040 13.095 1412.940 1423.745 ;
        RECT 1415.340 13.095 1416.240 1423.745 ;
        RECT 1418.640 13.095 1419.540 1423.745 ;
        RECT 1421.940 13.095 1422.840 1423.745 ;
        RECT 1425.240 13.095 1426.140 1423.745 ;
        RECT 1428.540 13.095 1492.370 1423.745 ;
      LAYER met5 ;
        RECT 67.740 665.750 1492.580 699.500 ;
        RECT 67.740 512.570 1492.580 637.850 ;
        RECT 67.740 359.390 1492.580 484.670 ;
        RECT 67.740 206.210 1492.580 331.490 ;
        RECT 67.740 85.900 1492.580 178.310 ;
  END
END rv32i_top
END LIBRARY

